VERSION 5.8 ;
BUSBITCHARS "[]" ;
DIVIDERCHAR "/" ;
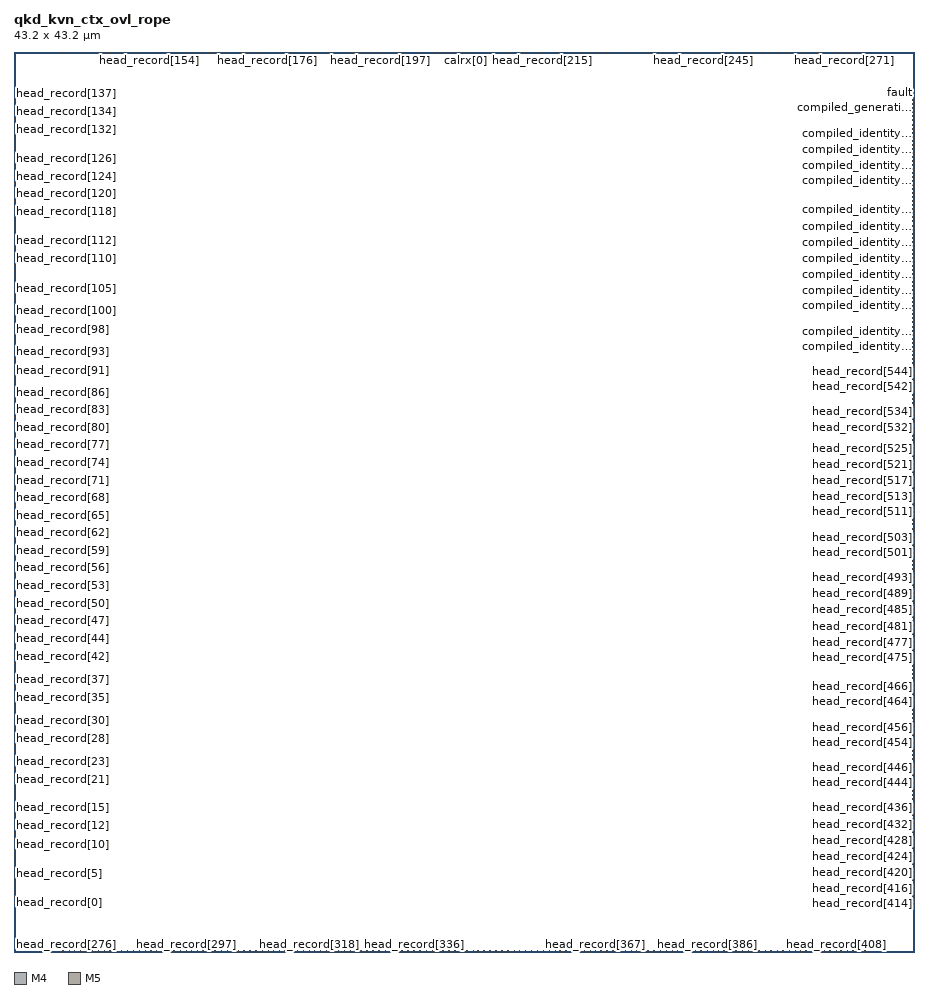
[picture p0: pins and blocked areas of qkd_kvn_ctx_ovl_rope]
MACRO qkd_kvn_ctx_ovl_rope
  CLASS BLOCK ;
  ORIGIN 0 0 ;
  SIZE 43.200000 BY 43.200000 ;
  SYMMETRY X Y ;
  PIN head_record[0]
    DIRECTION INPUT ;
    USE SIGNAL ;
    PORT
      LAYER M4 ;
      RECT 0.000000 2.352000 0.084000 2.376000 ;
    END
  END head_record[0]
  PIN head_record[1]
    DIRECTION INPUT ;
    USE SIGNAL ;
    PORT
      LAYER M4 ;
      RECT 0.000000 2.640000 0.084000 2.664000 ;
    END
  END head_record[1]
  PIN head_record[2]
    DIRECTION INPUT ;
    USE SIGNAL ;
    PORT
      LAYER M4 ;
      RECT 0.000000 2.880000 0.084000 2.904000 ;
    END
  END head_record[2]
  PIN head_record[3]
    DIRECTION INPUT ;
    USE SIGNAL ;
    PORT
      LAYER M4 ;
      RECT 0.000000 3.168000 0.084000 3.192000 ;
    END
  END head_record[3]
  PIN head_record[4]
    DIRECTION INPUT ;
    USE SIGNAL ;
    PORT
      LAYER M4 ;
      RECT 0.000000 3.456000 0.084000 3.480000 ;
    END
  END head_record[4]
  PIN head_record[5]
    DIRECTION INPUT ;
    USE SIGNAL ;
    PORT
      LAYER M4 ;
      RECT 0.000000 3.744000 0.084000 3.768000 ;
    END
  END head_record[5]
  PIN head_record[6]
    DIRECTION INPUT ;
    USE SIGNAL ;
    PORT
      LAYER M4 ;
      RECT 0.000000 4.032000 0.084000 4.056000 ;
    END
  END head_record[6]
  PIN head_record[7]
    DIRECTION INPUT ;
    USE SIGNAL ;
    PORT
      LAYER M4 ;
      RECT 0.000000 4.320000 0.084000 4.344000 ;
    END
  END head_record[7]
  PIN head_record[8]
    DIRECTION INPUT ;
    USE SIGNAL ;
    PORT
      LAYER M4 ;
      RECT 0.000000 4.608000 0.084000 4.632000 ;
    END
  END head_record[8]
  PIN head_record[9]
    DIRECTION INPUT ;
    USE SIGNAL ;
    PORT
      LAYER M4 ;
      RECT 0.000000 4.848000 0.084000 4.872000 ;
    END
  END head_record[9]
  PIN head_record[10]
    DIRECTION INPUT ;
    USE SIGNAL ;
    PORT
      LAYER M4 ;
      RECT 0.000000 5.136000 0.084000 5.160000 ;
    END
  END head_record[10]
  PIN head_record[11]
    DIRECTION INPUT ;
    USE SIGNAL ;
    PORT
      LAYER M4 ;
      RECT 0.000000 5.424000 0.084000 5.448000 ;
    END
  END head_record[11]
  PIN head_record[12]
    DIRECTION INPUT ;
    USE SIGNAL ;
    PORT
      LAYER M4 ;
      RECT 0.000000 5.712000 0.084000 5.736000 ;
    END
  END head_record[12]
  PIN head_record[13]
    DIRECTION INPUT ;
    USE SIGNAL ;
    PORT
      LAYER M4 ;
      RECT 0.000000 6.000000 0.084000 6.024000 ;
    END
  END head_record[13]
  PIN head_record[14]
    DIRECTION INPUT ;
    USE SIGNAL ;
    PORT
      LAYER M4 ;
      RECT 0.000000 6.288000 0.084000 6.312000 ;
    END
  END head_record[14]
  PIN head_record[15]
    DIRECTION INPUT ;
    USE SIGNAL ;
    PORT
      LAYER M4 ;
      RECT 0.000000 6.576000 0.084000 6.600000 ;
    END
  END head_record[15]
  PIN head_record[16]
    DIRECTION INPUT ;
    USE SIGNAL ;
    PORT
      LAYER M4 ;
      RECT 0.000000 6.816000 0.084000 6.840000 ;
    END
  END head_record[16]
  PIN head_record[17]
    DIRECTION INPUT ;
    USE SIGNAL ;
    PORT
      LAYER M4 ;
      RECT 0.000000 7.104000 0.084000 7.128000 ;
    END
  END head_record[17]
  PIN head_record[18]
    DIRECTION INPUT ;
    USE SIGNAL ;
    PORT
      LAYER M4 ;
      RECT 0.000000 7.392000 0.084000 7.416000 ;
    END
  END head_record[18]
  PIN head_record[19]
    DIRECTION INPUT ;
    USE SIGNAL ;
    PORT
      LAYER M4 ;
      RECT 0.000000 7.680000 0.084000 7.704000 ;
    END
  END head_record[19]
  PIN head_record[20]
    DIRECTION INPUT ;
    USE SIGNAL ;
    PORT
      LAYER M4 ;
      RECT 0.000000 7.968000 0.084000 7.992000 ;
    END
  END head_record[20]
  PIN head_record[21]
    DIRECTION INPUT ;
    USE SIGNAL ;
    PORT
      LAYER M4 ;
      RECT 0.000000 8.256000 0.084000 8.280000 ;
    END
  END head_record[21]
  PIN head_record[22]
    DIRECTION INPUT ;
    USE SIGNAL ;
    PORT
      LAYER M4 ;
      RECT 0.000000 8.496000 0.084000 8.520000 ;
    END
  END head_record[22]
  PIN head_record[23]
    DIRECTION INPUT ;
    USE SIGNAL ;
    PORT
      LAYER M4 ;
      RECT 0.000000 8.784000 0.084000 8.808000 ;
    END
  END head_record[23]
  PIN head_record[24]
    DIRECTION INPUT ;
    USE SIGNAL ;
    PORT
      LAYER M4 ;
      RECT 0.000000 9.072000 0.084000 9.096000 ;
    END
  END head_record[24]
  PIN head_record[25]
    DIRECTION INPUT ;
    USE SIGNAL ;
    PORT
      LAYER M4 ;
      RECT 0.000000 9.360000 0.084000 9.384000 ;
    END
  END head_record[25]
  PIN head_record[26]
    DIRECTION INPUT ;
    USE SIGNAL ;
    PORT
      LAYER M4 ;
      RECT 0.000000 9.648000 0.084000 9.672000 ;
    END
  END head_record[26]
  PIN head_record[27]
    DIRECTION INPUT ;
    USE SIGNAL ;
    PORT
      LAYER M4 ;
      RECT 0.000000 9.936000 0.084000 9.960000 ;
    END
  END head_record[27]
  PIN head_record[28]
    DIRECTION INPUT ;
    USE SIGNAL ;
    PORT
      LAYER M4 ;
      RECT 0.000000 10.224000 0.084000 10.248000 ;
    END
  END head_record[28]
  PIN head_record[29]
    DIRECTION INPUT ;
    USE SIGNAL ;
    PORT
      LAYER M4 ;
      RECT 0.000000 10.464000 0.084000 10.488000 ;
    END
  END head_record[29]
  PIN head_record[30]
    DIRECTION INPUT ;
    USE SIGNAL ;
    PORT
      LAYER M4 ;
      RECT 0.000000 10.752000 0.084000 10.776000 ;
    END
  END head_record[30]
  PIN head_record[31]
    DIRECTION INPUT ;
    USE SIGNAL ;
    PORT
      LAYER M4 ;
      RECT 0.000000 11.040000 0.084000 11.064000 ;
    END
  END head_record[31]
  PIN head_record[32]
    DIRECTION INPUT ;
    USE SIGNAL ;
    PORT
      LAYER M4 ;
      RECT 0.000000 11.328000 0.084000 11.352000 ;
    END
  END head_record[32]
  PIN head_record[33]
    DIRECTION INPUT ;
    USE SIGNAL ;
    PORT
      LAYER M4 ;
      RECT 0.000000 11.616000 0.084000 11.640000 ;
    END
  END head_record[33]
  PIN head_record[34]
    DIRECTION INPUT ;
    USE SIGNAL ;
    PORT
      LAYER M4 ;
      RECT 0.000000 11.904000 0.084000 11.928000 ;
    END
  END head_record[34]
  PIN head_record[35]
    DIRECTION INPUT ;
    USE SIGNAL ;
    PORT
      LAYER M4 ;
      RECT 0.000000 12.192000 0.084000 12.216000 ;
    END
  END head_record[35]
  PIN head_record[36]
    DIRECTION INPUT ;
    USE SIGNAL ;
    PORT
      LAYER M4 ;
      RECT 0.000000 12.432000 0.084000 12.456000 ;
    END
  END head_record[36]
  PIN head_record[37]
    DIRECTION INPUT ;
    USE SIGNAL ;
    PORT
      LAYER M4 ;
      RECT 0.000000 12.720000 0.084000 12.744000 ;
    END
  END head_record[37]
  PIN head_record[38]
    DIRECTION INPUT ;
    USE SIGNAL ;
    PORT
      LAYER M4 ;
      RECT 0.000000 13.008000 0.084000 13.032000 ;
    END
  END head_record[38]
  PIN head_record[39]
    DIRECTION INPUT ;
    USE SIGNAL ;
    PORT
      LAYER M4 ;
      RECT 0.000000 13.296000 0.084000 13.320000 ;
    END
  END head_record[39]
  PIN head_record[40]
    DIRECTION INPUT ;
    USE SIGNAL ;
    PORT
      LAYER M4 ;
      RECT 0.000000 13.584000 0.084000 13.608000 ;
    END
  END head_record[40]
  PIN head_record[41]
    DIRECTION INPUT ;
    USE SIGNAL ;
    PORT
      LAYER M4 ;
      RECT 0.000000 13.872000 0.084000 13.896000 ;
    END
  END head_record[41]
  PIN head_record[42]
    DIRECTION INPUT ;
    USE SIGNAL ;
    PORT
      LAYER M4 ;
      RECT 0.000000 14.160000 0.084000 14.184000 ;
    END
  END head_record[42]
  PIN head_record[43]
    DIRECTION INPUT ;
    USE SIGNAL ;
    PORT
      LAYER M4 ;
      RECT 0.000000 14.400000 0.084000 14.424000 ;
    END
  END head_record[43]
  PIN head_record[44]
    DIRECTION INPUT ;
    USE SIGNAL ;
    PORT
      LAYER M4 ;
      RECT 0.000000 14.688000 0.084000 14.712000 ;
    END
  END head_record[44]
  PIN head_record[45]
    DIRECTION INPUT ;
    USE SIGNAL ;
    PORT
      LAYER M4 ;
      RECT 0.000000 14.976000 0.084000 15.000000 ;
    END
  END head_record[45]
  PIN head_record[46]
    DIRECTION INPUT ;
    USE SIGNAL ;
    PORT
      LAYER M4 ;
      RECT 0.000000 15.264000 0.084000 15.288000 ;
    END
  END head_record[46]
  PIN head_record[47]
    DIRECTION INPUT ;
    USE SIGNAL ;
    PORT
      LAYER M4 ;
      RECT 0.000000 15.552000 0.084000 15.576000 ;
    END
  END head_record[47]
  PIN head_record[48]
    DIRECTION INPUT ;
    USE SIGNAL ;
    PORT
      LAYER M4 ;
      RECT 0.000000 15.840000 0.084000 15.864000 ;
    END
  END head_record[48]
  PIN head_record[49]
    DIRECTION INPUT ;
    USE SIGNAL ;
    PORT
      LAYER M4 ;
      RECT 0.000000 16.128000 0.084000 16.152000 ;
    END
  END head_record[49]
  PIN head_record[50]
    DIRECTION INPUT ;
    USE SIGNAL ;
    PORT
      LAYER M4 ;
      RECT 0.000000 16.368000 0.084000 16.392000 ;
    END
  END head_record[50]
  PIN head_record[51]
    DIRECTION INPUT ;
    USE SIGNAL ;
    PORT
      LAYER M4 ;
      RECT 0.000000 16.656000 0.084000 16.680000 ;
    END
  END head_record[51]
  PIN head_record[52]
    DIRECTION INPUT ;
    USE SIGNAL ;
    PORT
      LAYER M4 ;
      RECT 0.000000 16.944000 0.084000 16.968000 ;
    END
  END head_record[52]
  PIN head_record[53]
    DIRECTION INPUT ;
    USE SIGNAL ;
    PORT
      LAYER M4 ;
      RECT 0.000000 17.232000 0.084000 17.256000 ;
    END
  END head_record[53]
  PIN head_record[54]
    DIRECTION INPUT ;
    USE SIGNAL ;
    PORT
      LAYER M4 ;
      RECT 0.000000 17.520000 0.084000 17.544000 ;
    END
  END head_record[54]
  PIN head_record[55]
    DIRECTION INPUT ;
    USE SIGNAL ;
    PORT
      LAYER M4 ;
      RECT 0.000000 17.808000 0.084000 17.832000 ;
    END
  END head_record[55]
  PIN head_record[56]
    DIRECTION INPUT ;
    USE SIGNAL ;
    PORT
      LAYER M4 ;
      RECT 0.000000 18.096000 0.084000 18.120000 ;
    END
  END head_record[56]
  PIN head_record[57]
    DIRECTION INPUT ;
    USE SIGNAL ;
    PORT
      LAYER M4 ;
      RECT 0.000000 18.336000 0.084000 18.360000 ;
    END
  END head_record[57]
  PIN head_record[58]
    DIRECTION INPUT ;
    USE SIGNAL ;
    PORT
      LAYER M4 ;
      RECT 0.000000 18.624000 0.084000 18.648000 ;
    END
  END head_record[58]
  PIN head_record[59]
    DIRECTION INPUT ;
    USE SIGNAL ;
    PORT
      LAYER M4 ;
      RECT 0.000000 18.912000 0.084000 18.936000 ;
    END
  END head_record[59]
  PIN head_record[60]
    DIRECTION INPUT ;
    USE SIGNAL ;
    PORT
      LAYER M4 ;
      RECT 0.000000 19.200000 0.084000 19.224000 ;
    END
  END head_record[60]
  PIN head_record[61]
    DIRECTION INPUT ;
    USE SIGNAL ;
    PORT
      LAYER M4 ;
      RECT 0.000000 19.488000 0.084000 19.512000 ;
    END
  END head_record[61]
  PIN head_record[62]
    DIRECTION INPUT ;
    USE SIGNAL ;
    PORT
      LAYER M4 ;
      RECT 0.000000 19.776000 0.084000 19.800000 ;
    END
  END head_record[62]
  PIN head_record[63]
    DIRECTION INPUT ;
    USE SIGNAL ;
    PORT
      LAYER M4 ;
      RECT 0.000000 20.064000 0.084000 20.088000 ;
    END
  END head_record[63]
  PIN head_record[64]
    DIRECTION INPUT ;
    USE SIGNAL ;
    PORT
      LAYER M4 ;
      RECT 0.000000 20.304000 0.084000 20.328000 ;
    END
  END head_record[64]
  PIN head_record[65]
    DIRECTION INPUT ;
    USE SIGNAL ;
    PORT
      LAYER M4 ;
      RECT 0.000000 20.592000 0.084000 20.616000 ;
    END
  END head_record[65]
  PIN head_record[66]
    DIRECTION INPUT ;
    USE SIGNAL ;
    PORT
      LAYER M4 ;
      RECT 0.000000 20.880000 0.084000 20.904000 ;
    END
  END head_record[66]
  PIN head_record[67]
    DIRECTION INPUT ;
    USE SIGNAL ;
    PORT
      LAYER M4 ;
      RECT 0.000000 21.168000 0.084000 21.192000 ;
    END
  END head_record[67]
  PIN head_record[68]
    DIRECTION INPUT ;
    USE SIGNAL ;
    PORT
      LAYER M4 ;
      RECT 0.000000 21.456000 0.084000 21.480000 ;
    END
  END head_record[68]
  PIN head_record[69]
    DIRECTION INPUT ;
    USE SIGNAL ;
    PORT
      LAYER M4 ;
      RECT 0.000000 21.744000 0.084000 21.768000 ;
    END
  END head_record[69]
  PIN head_record[70]
    DIRECTION INPUT ;
    USE SIGNAL ;
    PORT
      LAYER M4 ;
      RECT 0.000000 22.032000 0.084000 22.056000 ;
    END
  END head_record[70]
  PIN head_record[71]
    DIRECTION INPUT ;
    USE SIGNAL ;
    PORT
      LAYER M4 ;
      RECT 0.000000 22.272000 0.084000 22.296000 ;
    END
  END head_record[71]
  PIN head_record[72]
    DIRECTION INPUT ;
    USE SIGNAL ;
    PORT
      LAYER M4 ;
      RECT 0.000000 22.560000 0.084000 22.584000 ;
    END
  END head_record[72]
  PIN head_record[73]
    DIRECTION INPUT ;
    USE SIGNAL ;
    PORT
      LAYER M4 ;
      RECT 0.000000 22.848000 0.084000 22.872000 ;
    END
  END head_record[73]
  PIN head_record[74]
    DIRECTION INPUT ;
    USE SIGNAL ;
    PORT
      LAYER M4 ;
      RECT 0.000000 23.136000 0.084000 23.160000 ;
    END
  END head_record[74]
  PIN head_record[75]
    DIRECTION INPUT ;
    USE SIGNAL ;
    PORT
      LAYER M4 ;
      RECT 0.000000 23.424000 0.084000 23.448000 ;
    END
  END head_record[75]
  PIN head_record[76]
    DIRECTION INPUT ;
    USE SIGNAL ;
    PORT
      LAYER M4 ;
      RECT 0.000000 23.712000 0.084000 23.736000 ;
    END
  END head_record[76]
  PIN head_record[77]
    DIRECTION INPUT ;
    USE SIGNAL ;
    PORT
      LAYER M4 ;
      RECT 0.000000 24.000000 0.084000 24.024000 ;
    END
  END head_record[77]
  PIN head_record[78]
    DIRECTION INPUT ;
    USE SIGNAL ;
    PORT
      LAYER M4 ;
      RECT 0.000000 24.240000 0.084000 24.264000 ;
    END
  END head_record[78]
  PIN head_record[79]
    DIRECTION INPUT ;
    USE SIGNAL ;
    PORT
      LAYER M4 ;
      RECT 0.000000 24.528000 0.084000 24.552000 ;
    END
  END head_record[79]
  PIN head_record[80]
    DIRECTION INPUT ;
    USE SIGNAL ;
    PORT
      LAYER M4 ;
      RECT 0.000000 24.816000 0.084000 24.840000 ;
    END
  END head_record[80]
  PIN head_record[81]
    DIRECTION INPUT ;
    USE SIGNAL ;
    PORT
      LAYER M4 ;
      RECT 0.000000 25.104000 0.084000 25.128000 ;
    END
  END head_record[81]
  PIN head_record[82]
    DIRECTION INPUT ;
    USE SIGNAL ;
    PORT
      LAYER M4 ;
      RECT 0.000000 25.392000 0.084000 25.416000 ;
    END
  END head_record[82]
  PIN head_record[83]
    DIRECTION INPUT ;
    USE SIGNAL ;
    PORT
      LAYER M4 ;
      RECT 0.000000 25.680000 0.084000 25.704000 ;
    END
  END head_record[83]
  PIN head_record[84]
    DIRECTION INPUT ;
    USE SIGNAL ;
    PORT
      LAYER M4 ;
      RECT 0.000000 25.968000 0.084000 25.992000 ;
    END
  END head_record[84]
  PIN head_record[85]
    DIRECTION INPUT ;
    USE SIGNAL ;
    PORT
      LAYER M4 ;
      RECT 0.000000 26.208000 0.084000 26.232000 ;
    END
  END head_record[85]
  PIN head_record[86]
    DIRECTION INPUT ;
    USE SIGNAL ;
    PORT
      LAYER M4 ;
      RECT 0.000000 26.496000 0.084000 26.520000 ;
    END
  END head_record[86]
  PIN head_record[87]
    DIRECTION INPUT ;
    USE SIGNAL ;
    PORT
      LAYER M4 ;
      RECT 0.000000 26.784000 0.084000 26.808000 ;
    END
  END head_record[87]
  PIN head_record[88]
    DIRECTION INPUT ;
    USE SIGNAL ;
    PORT
      LAYER M4 ;
      RECT 0.000000 27.072000 0.084000 27.096000 ;
    END
  END head_record[88]
  PIN head_record[89]
    DIRECTION INPUT ;
    USE SIGNAL ;
    PORT
      LAYER M4 ;
      RECT 0.000000 27.360000 0.084000 27.384000 ;
    END
  END head_record[89]
  PIN head_record[90]
    DIRECTION INPUT ;
    USE SIGNAL ;
    PORT
      LAYER M4 ;
      RECT 0.000000 27.648000 0.084000 27.672000 ;
    END
  END head_record[90]
  PIN head_record[91]
    DIRECTION INPUT ;
    USE SIGNAL ;
    PORT
      LAYER M4 ;
      RECT 0.000000 27.888000 0.084000 27.912000 ;
    END
  END head_record[91]
  PIN head_record[92]
    DIRECTION INPUT ;
    USE SIGNAL ;
    PORT
      LAYER M4 ;
      RECT 0.000000 28.176000 0.084000 28.200000 ;
    END
  END head_record[92]
  PIN head_record[93]
    DIRECTION INPUT ;
    USE SIGNAL ;
    PORT
      LAYER M4 ;
      RECT 0.000000 28.464000 0.084000 28.488000 ;
    END
  END head_record[93]
  PIN head_record[94]
    DIRECTION INPUT ;
    USE SIGNAL ;
    PORT
      LAYER M4 ;
      RECT 0.000000 28.752000 0.084000 28.776000 ;
    END
  END head_record[94]
  PIN head_record[95]
    DIRECTION INPUT ;
    USE SIGNAL ;
    PORT
      LAYER M4 ;
      RECT 0.000000 29.040000 0.084000 29.064000 ;
    END
  END head_record[95]
  PIN head_record[96]
    DIRECTION INPUT ;
    USE SIGNAL ;
    PORT
      LAYER M4 ;
      RECT 0.000000 29.328000 0.084000 29.352000 ;
    END
  END head_record[96]
  PIN head_record[97]
    DIRECTION INPUT ;
    USE SIGNAL ;
    PORT
      LAYER M4 ;
      RECT 0.000000 29.616000 0.084000 29.640000 ;
    END
  END head_record[97]
  PIN head_record[98]
    DIRECTION INPUT ;
    USE SIGNAL ;
    PORT
      LAYER M4 ;
      RECT 0.000000 29.856000 0.084000 29.880000 ;
    END
  END head_record[98]
  PIN head_record[99]
    DIRECTION INPUT ;
    USE SIGNAL ;
    PORT
      LAYER M4 ;
      RECT 0.000000 30.144000 0.084000 30.168000 ;
    END
  END head_record[99]
  PIN head_record[100]
    DIRECTION INPUT ;
    USE SIGNAL ;
    PORT
      LAYER M4 ;
      RECT 0.000000 30.432000 0.084000 30.456000 ;
    END
  END head_record[100]
  PIN head_record[101]
    DIRECTION INPUT ;
    USE SIGNAL ;
    PORT
      LAYER M4 ;
      RECT 0.000000 30.720000 0.084000 30.744000 ;
    END
  END head_record[101]
  PIN head_record[102]
    DIRECTION INPUT ;
    USE SIGNAL ;
    PORT
      LAYER M4 ;
      RECT 0.000000 31.008000 0.084000 31.032000 ;
    END
  END head_record[102]
  PIN head_record[103]
    DIRECTION INPUT ;
    USE SIGNAL ;
    PORT
      LAYER M4 ;
      RECT 0.000000 31.296000 0.084000 31.320000 ;
    END
  END head_record[103]
  PIN head_record[104]
    DIRECTION INPUT ;
    USE SIGNAL ;
    PORT
      LAYER M4 ;
      RECT 0.000000 31.584000 0.084000 31.608000 ;
    END
  END head_record[104]
  PIN head_record[105]
    DIRECTION INPUT ;
    USE SIGNAL ;
    PORT
      LAYER M4 ;
      RECT 0.000000 31.824000 0.084000 31.848000 ;
    END
  END head_record[105]
  PIN head_record[106]
    DIRECTION INPUT ;
    USE SIGNAL ;
    PORT
      LAYER M4 ;
      RECT 0.000000 32.112000 0.084000 32.136000 ;
    END
  END head_record[106]
  PIN head_record[107]
    DIRECTION INPUT ;
    USE SIGNAL ;
    PORT
      LAYER M4 ;
      RECT 0.000000 32.400000 0.084000 32.424000 ;
    END
  END head_record[107]
  PIN head_record[108]
    DIRECTION INPUT ;
    USE SIGNAL ;
    PORT
      LAYER M4 ;
      RECT 0.000000 32.688000 0.084000 32.712000 ;
    END
  END head_record[108]
  PIN head_record[109]
    DIRECTION INPUT ;
    USE SIGNAL ;
    PORT
      LAYER M4 ;
      RECT 0.000000 32.976000 0.084000 33.000000 ;
    END
  END head_record[109]
  PIN head_record[110]
    DIRECTION INPUT ;
    USE SIGNAL ;
    PORT
      LAYER M4 ;
      RECT 0.000000 33.264000 0.084000 33.288000 ;
    END
  END head_record[110]
  PIN head_record[111]
    DIRECTION INPUT ;
    USE SIGNAL ;
    PORT
      LAYER M4 ;
      RECT 0.000000 33.552000 0.084000 33.576000 ;
    END
  END head_record[111]
  PIN head_record[112]
    DIRECTION INPUT ;
    USE SIGNAL ;
    PORT
      LAYER M4 ;
      RECT 0.000000 33.792000 0.084000 33.816000 ;
    END
  END head_record[112]
  PIN head_record[113]
    DIRECTION INPUT ;
    USE SIGNAL ;
    PORT
      LAYER M4 ;
      RECT 0.000000 34.080000 0.084000 34.104000 ;
    END
  END head_record[113]
  PIN head_record[114]
    DIRECTION INPUT ;
    USE SIGNAL ;
    PORT
      LAYER M4 ;
      RECT 0.000000 34.368000 0.084000 34.392000 ;
    END
  END head_record[114]
  PIN head_record[115]
    DIRECTION INPUT ;
    USE SIGNAL ;
    PORT
      LAYER M4 ;
      RECT 0.000000 34.656000 0.084000 34.680000 ;
    END
  END head_record[115]
  PIN head_record[116]
    DIRECTION INPUT ;
    USE SIGNAL ;
    PORT
      LAYER M4 ;
      RECT 0.000000 34.944000 0.084000 34.968000 ;
    END
  END head_record[116]
  PIN head_record[117]
    DIRECTION INPUT ;
    USE SIGNAL ;
    PORT
      LAYER M4 ;
      RECT 0.000000 35.232000 0.084000 35.256000 ;
    END
  END head_record[117]
  PIN head_record[118]
    DIRECTION INPUT ;
    USE SIGNAL ;
    PORT
      LAYER M4 ;
      RECT 0.000000 35.520000 0.084000 35.544000 ;
    END
  END head_record[118]
  PIN head_record[119]
    DIRECTION INPUT ;
    USE SIGNAL ;
    PORT
      LAYER M4 ;
      RECT 0.000000 35.760000 0.084000 35.784000 ;
    END
  END head_record[119]
  PIN head_record[120]
    DIRECTION INPUT ;
    USE SIGNAL ;
    PORT
      LAYER M4 ;
      RECT 0.000000 36.048000 0.084000 36.072000 ;
    END
  END head_record[120]
  PIN head_record[121]
    DIRECTION INPUT ;
    USE SIGNAL ;
    PORT
      LAYER M4 ;
      RECT 0.000000 36.336000 0.084000 36.360000 ;
    END
  END head_record[121]
  PIN head_record[122]
    DIRECTION INPUT ;
    USE SIGNAL ;
    PORT
      LAYER M4 ;
      RECT 0.000000 36.624000 0.084000 36.648000 ;
    END
  END head_record[122]
  PIN head_record[123]
    DIRECTION INPUT ;
    USE SIGNAL ;
    PORT
      LAYER M4 ;
      RECT 0.000000 36.912000 0.084000 36.936000 ;
    END
  END head_record[123]
  PIN head_record[124]
    DIRECTION INPUT ;
    USE SIGNAL ;
    PORT
      LAYER M4 ;
      RECT 0.000000 37.200000 0.084000 37.224000 ;
    END
  END head_record[124]
  PIN head_record[125]
    DIRECTION INPUT ;
    USE SIGNAL ;
    PORT
      LAYER M4 ;
      RECT 0.000000 37.488000 0.084000 37.512000 ;
    END
  END head_record[125]
  PIN head_record[126]
    DIRECTION INPUT ;
    USE SIGNAL ;
    PORT
      LAYER M4 ;
      RECT 0.000000 37.728000 0.084000 37.752000 ;
    END
  END head_record[126]
  PIN head_record[127]
    DIRECTION INPUT ;
    USE SIGNAL ;
    PORT
      LAYER M4 ;
      RECT 0.000000 38.016000 0.084000 38.040000 ;
    END
  END head_record[127]
  PIN head_record[128]
    DIRECTION INPUT ;
    USE SIGNAL ;
    PORT
      LAYER M4 ;
      RECT 0.000000 38.304000 0.084000 38.328000 ;
    END
  END head_record[128]
  PIN head_record[129]
    DIRECTION INPUT ;
    USE SIGNAL ;
    PORT
      LAYER M4 ;
      RECT 0.000000 38.592000 0.084000 38.616000 ;
    END
  END head_record[129]
  PIN head_record[130]
    DIRECTION INPUT ;
    USE SIGNAL ;
    PORT
      LAYER M4 ;
      RECT 0.000000 38.880000 0.084000 38.904000 ;
    END
  END head_record[130]
  PIN head_record[131]
    DIRECTION INPUT ;
    USE SIGNAL ;
    PORT
      LAYER M4 ;
      RECT 0.000000 39.168000 0.084000 39.192000 ;
    END
  END head_record[131]
  PIN head_record[132]
    DIRECTION INPUT ;
    USE SIGNAL ;
    PORT
      LAYER M4 ;
      RECT 0.000000 39.456000 0.084000 39.480000 ;
    END
  END head_record[132]
  PIN head_record[133]
    DIRECTION INPUT ;
    USE SIGNAL ;
    PORT
      LAYER M4 ;
      RECT 0.000000 39.696000 0.084000 39.720000 ;
    END
  END head_record[133]
  PIN head_record[134]
    DIRECTION INPUT ;
    USE SIGNAL ;
    PORT
      LAYER M4 ;
      RECT 0.000000 39.984000 0.084000 40.008000 ;
    END
  END head_record[134]
  PIN head_record[135]
    DIRECTION INPUT ;
    USE SIGNAL ;
    PORT
      LAYER M4 ;
      RECT 0.000000 40.272000 0.084000 40.296000 ;
    END
  END head_record[135]
  PIN head_record[136]
    DIRECTION INPUT ;
    USE SIGNAL ;
    PORT
      LAYER M4 ;
      RECT 0.000000 40.560000 0.084000 40.584000 ;
    END
  END head_record[136]
  PIN head_record[137]
    DIRECTION INPUT ;
    USE SIGNAL ;
    PORT
      LAYER M4 ;
      RECT 0.000000 40.848000 0.084000 40.872000 ;
    END
  END head_record[137]
  PIN head_record[138]
    DIRECTION INPUT ;
    USE SIGNAL ;
    PORT
      LAYER M5 ;
      RECT 2.304000 43.116000 2.328000 43.200000 ;
    END
  END head_record[138]
  PIN head_record[139]
    DIRECTION INPUT ;
    USE SIGNAL ;
    PORT
      LAYER M5 ;
      RECT 2.592000 43.116000 2.616000 43.200000 ;
    END
  END head_record[139]
  PIN head_record[140]
    DIRECTION INPUT ;
    USE SIGNAL ;
    PORT
      LAYER M5 ;
      RECT 2.832000 43.116000 2.856000 43.200000 ;
    END
  END head_record[140]
  PIN head_record[141]
    DIRECTION INPUT ;
    USE SIGNAL ;
    PORT
      LAYER M5 ;
      RECT 3.120000 43.116000 3.144000 43.200000 ;
    END
  END head_record[141]
  PIN head_record[142]
    DIRECTION INPUT ;
    USE SIGNAL ;
    PORT
      LAYER M5 ;
      RECT 3.360000 43.116000 3.384000 43.200000 ;
    END
  END head_record[142]
  PIN head_record[143]
    DIRECTION INPUT ;
    USE SIGNAL ;
    PORT
      LAYER M5 ;
      RECT 3.600000 43.116000 3.624000 43.200000 ;
    END
  END head_record[143]
  PIN head_record[144]
    DIRECTION INPUT ;
    USE SIGNAL ;
    PORT
      LAYER M5 ;
      RECT 3.888000 43.116000 3.912000 43.200000 ;
    END
  END head_record[144]
  PIN head_record[145]
    DIRECTION INPUT ;
    USE SIGNAL ;
    PORT
      LAYER M5 ;
      RECT 4.128000 43.116000 4.152000 43.200000 ;
    END
  END head_record[145]
  PIN head_record[146]
    DIRECTION INPUT ;
    USE SIGNAL ;
    PORT
      LAYER M5 ;
      RECT 4.416000 43.116000 4.440000 43.200000 ;
    END
  END head_record[146]
  PIN head_record[147]
    DIRECTION INPUT ;
    USE SIGNAL ;
    PORT
      LAYER M5 ;
      RECT 4.656000 43.116000 4.680000 43.200000 ;
    END
  END head_record[147]
  PIN head_record[148]
    DIRECTION INPUT ;
    USE SIGNAL ;
    PORT
      LAYER M5 ;
      RECT 4.896000 43.116000 4.920000 43.200000 ;
    END
  END head_record[148]
  PIN head_record[149]
    DIRECTION INPUT ;
    USE SIGNAL ;
    PORT
      LAYER M5 ;
      RECT 5.184000 43.116000 5.208000 43.200000 ;
    END
  END head_record[149]
  PIN head_record[150]
    DIRECTION INPUT ;
    USE SIGNAL ;
    PORT
      LAYER M5 ;
      RECT 5.424000 43.116000 5.448000 43.200000 ;
    END
  END head_record[150]
  PIN head_record[151]
    DIRECTION INPUT ;
    USE SIGNAL ;
    PORT
      LAYER M5 ;
      RECT 5.664000 43.116000 5.688000 43.200000 ;
    END
  END head_record[151]
  PIN head_record[152]
    DIRECTION INPUT ;
    USE SIGNAL ;
    PORT
      LAYER M5 ;
      RECT 5.952000 43.116000 5.976000 43.200000 ;
    END
  END head_record[152]
  PIN head_record[153]
    DIRECTION INPUT ;
    USE SIGNAL ;
    PORT
      LAYER M5 ;
      RECT 6.192000 43.116000 6.216000 43.200000 ;
    END
  END head_record[153]
  PIN head_record[154]
    DIRECTION INPUT ;
    USE SIGNAL ;
    PORT
      LAYER M5 ;
      RECT 6.480000 43.116000 6.504000 43.200000 ;
    END
  END head_record[154]
  PIN head_record[155]
    DIRECTION INPUT ;
    USE SIGNAL ;
    PORT
      LAYER M5 ;
      RECT 6.720000 43.116000 6.744000 43.200000 ;
    END
  END head_record[155]
  PIN head_record[156]
    DIRECTION INPUT ;
    USE SIGNAL ;
    PORT
      LAYER M5 ;
      RECT 6.960000 43.116000 6.984000 43.200000 ;
    END
  END head_record[156]
  PIN head_record[157]
    DIRECTION INPUT ;
    USE SIGNAL ;
    PORT
      LAYER M5 ;
      RECT 7.248000 43.116000 7.272000 43.200000 ;
    END
  END head_record[157]
  PIN head_record[158]
    DIRECTION INPUT ;
    USE SIGNAL ;
    PORT
      LAYER M5 ;
      RECT 7.488000 43.116000 7.512000 43.200000 ;
    END
  END head_record[158]
  PIN head_record[159]
    DIRECTION INPUT ;
    USE SIGNAL ;
    PORT
      LAYER M5 ;
      RECT 7.776000 43.116000 7.800000 43.200000 ;
    END
  END head_record[159]
  PIN head_record[160]
    DIRECTION INPUT ;
    USE SIGNAL ;
    PORT
      LAYER M5 ;
      RECT 8.016000 43.116000 8.040000 43.200000 ;
    END
  END head_record[160]
  PIN head_record[161]
    DIRECTION INPUT ;
    USE SIGNAL ;
    PORT
      LAYER M5 ;
      RECT 8.256000 43.116000 8.280000 43.200000 ;
    END
  END head_record[161]
  PIN head_record[162]
    DIRECTION INPUT ;
    USE SIGNAL ;
    PORT
      LAYER M5 ;
      RECT 8.544000 43.116000 8.568000 43.200000 ;
    END
  END head_record[162]
  PIN head_record[163]
    DIRECTION INPUT ;
    USE SIGNAL ;
    PORT
      LAYER M5 ;
      RECT 8.784000 43.116000 8.808000 43.200000 ;
    END
  END head_record[163]
  PIN head_record[164]
    DIRECTION INPUT ;
    USE SIGNAL ;
    PORT
      LAYER M5 ;
      RECT 9.024000 43.116000 9.048000 43.200000 ;
    END
  END head_record[164]
  PIN head_record[165]
    DIRECTION INPUT ;
    USE SIGNAL ;
    PORT
      LAYER M5 ;
      RECT 9.312000 43.116000 9.336000 43.200000 ;
    END
  END head_record[165]
  PIN head_record[166]
    DIRECTION INPUT ;
    USE SIGNAL ;
    PORT
      LAYER M5 ;
      RECT 9.552000 43.116000 9.576000 43.200000 ;
    END
  END head_record[166]
  PIN head_record[167]
    DIRECTION INPUT ;
    USE SIGNAL ;
    PORT
      LAYER M5 ;
      RECT 9.840000 43.116000 9.864000 43.200000 ;
    END
  END head_record[167]
  PIN head_record[168]
    DIRECTION INPUT ;
    USE SIGNAL ;
    PORT
      LAYER M5 ;
      RECT 10.080000 43.116000 10.104000 43.200000 ;
    END
  END head_record[168]
  PIN head_record[169]
    DIRECTION INPUT ;
    USE SIGNAL ;
    PORT
      LAYER M5 ;
      RECT 10.320000 43.116000 10.344000 43.200000 ;
    END
  END head_record[169]
  PIN head_record[170]
    DIRECTION INPUT ;
    USE SIGNAL ;
    PORT
      LAYER M5 ;
      RECT 10.608000 43.116000 10.632000 43.200000 ;
    END
  END head_record[170]
  PIN head_record[171]
    DIRECTION INPUT ;
    USE SIGNAL ;
    PORT
      LAYER M5 ;
      RECT 10.848000 43.116000 10.872000 43.200000 ;
    END
  END head_record[171]
  PIN head_record[172]
    DIRECTION INPUT ;
    USE SIGNAL ;
    PORT
      LAYER M5 ;
      RECT 11.136000 43.116000 11.160000 43.200000 ;
    END
  END head_record[172]
  PIN head_record[173]
    DIRECTION INPUT ;
    USE SIGNAL ;
    PORT
      LAYER M5 ;
      RECT 11.376000 43.116000 11.400000 43.200000 ;
    END
  END head_record[173]
  PIN head_record[174]
    DIRECTION INPUT ;
    USE SIGNAL ;
    PORT
      LAYER M5 ;
      RECT 11.616000 43.116000 11.640000 43.200000 ;
    END
  END head_record[174]
  PIN head_record[175]
    DIRECTION INPUT ;
    USE SIGNAL ;
    PORT
      LAYER M5 ;
      RECT 11.904000 43.116000 11.928000 43.200000 ;
    END
  END head_record[175]
  PIN head_record[176]
    DIRECTION INPUT ;
    USE SIGNAL ;
    PORT
      LAYER M5 ;
      RECT 12.144000 43.116000 12.168000 43.200000 ;
    END
  END head_record[176]
  PIN head_record[177]
    DIRECTION INPUT ;
    USE SIGNAL ;
    PORT
      LAYER M5 ;
      RECT 12.432000 43.116000 12.456000 43.200000 ;
    END
  END head_record[177]
  PIN head_record[178]
    DIRECTION INPUT ;
    USE SIGNAL ;
    PORT
      LAYER M5 ;
      RECT 12.672000 43.116000 12.696000 43.200000 ;
    END
  END head_record[178]
  PIN head_record[179]
    DIRECTION INPUT ;
    USE SIGNAL ;
    PORT
      LAYER M5 ;
      RECT 12.912000 43.116000 12.936000 43.200000 ;
    END
  END head_record[179]
  PIN head_record[180]
    DIRECTION INPUT ;
    USE SIGNAL ;
    PORT
      LAYER M5 ;
      RECT 13.200000 43.116000 13.224000 43.200000 ;
    END
  END head_record[180]
  PIN head_record[181]
    DIRECTION INPUT ;
    USE SIGNAL ;
    PORT
      LAYER M5 ;
      RECT 13.440000 43.116000 13.464000 43.200000 ;
    END
  END head_record[181]
  PIN head_record[182]
    DIRECTION INPUT ;
    USE SIGNAL ;
    PORT
      LAYER M5 ;
      RECT 13.680000 43.116000 13.704000 43.200000 ;
    END
  END head_record[182]
  PIN head_record[183]
    DIRECTION INPUT ;
    USE SIGNAL ;
    PORT
      LAYER M5 ;
      RECT 13.968000 43.116000 13.992000 43.200000 ;
    END
  END head_record[183]
  PIN head_record[184]
    DIRECTION INPUT ;
    USE SIGNAL ;
    PORT
      LAYER M5 ;
      RECT 14.208000 43.116000 14.232000 43.200000 ;
    END
  END head_record[184]
  PIN head_record[185]
    DIRECTION INPUT ;
    USE SIGNAL ;
    PORT
      LAYER M5 ;
      RECT 14.496000 43.116000 14.520000 43.200000 ;
    END
  END head_record[185]
  PIN head_record[186]
    DIRECTION INPUT ;
    USE SIGNAL ;
    PORT
      LAYER M5 ;
      RECT 14.736000 43.116000 14.760000 43.200000 ;
    END
  END head_record[186]
  PIN head_record[187]
    DIRECTION INPUT ;
    USE SIGNAL ;
    PORT
      LAYER M5 ;
      RECT 14.976000 43.116000 15.000000 43.200000 ;
    END
  END head_record[187]
  PIN head_record[188]
    DIRECTION INPUT ;
    USE SIGNAL ;
    PORT
      LAYER M5 ;
      RECT 15.264000 43.116000 15.288000 43.200000 ;
    END
  END head_record[188]
  PIN head_record[189]
    DIRECTION INPUT ;
    USE SIGNAL ;
    PORT
      LAYER M5 ;
      RECT 15.504000 43.116000 15.528000 43.200000 ;
    END
  END head_record[189]
  PIN head_record[190]
    DIRECTION INPUT ;
    USE SIGNAL ;
    PORT
      LAYER M5 ;
      RECT 15.792000 43.116000 15.816000 43.200000 ;
    END
  END head_record[190]
  PIN head_record[191]
    DIRECTION INPUT ;
    USE SIGNAL ;
    PORT
      LAYER M5 ;
      RECT 16.032000 43.116000 16.056000 43.200000 ;
    END
  END head_record[191]
  PIN head_record[192]
    DIRECTION INPUT ;
    USE SIGNAL ;
    PORT
      LAYER M5 ;
      RECT 16.272000 43.116000 16.296000 43.200000 ;
    END
  END head_record[192]
  PIN head_record[193]
    DIRECTION INPUT ;
    USE SIGNAL ;
    PORT
      LAYER M5 ;
      RECT 16.560000 43.116000 16.584000 43.200000 ;
    END
  END head_record[193]
  PIN head_record[194]
    DIRECTION INPUT ;
    USE SIGNAL ;
    PORT
      LAYER M5 ;
      RECT 16.800000 43.116000 16.824000 43.200000 ;
    END
  END head_record[194]
  PIN head_record[195]
    DIRECTION INPUT ;
    USE SIGNAL ;
    PORT
      LAYER M5 ;
      RECT 17.040000 43.116000 17.064000 43.200000 ;
    END
  END head_record[195]
  PIN head_record[196]
    DIRECTION INPUT ;
    USE SIGNAL ;
    PORT
      LAYER M5 ;
      RECT 17.328000 43.116000 17.352000 43.200000 ;
    END
  END head_record[196]
  PIN head_record[197]
    DIRECTION INPUT ;
    USE SIGNAL ;
    PORT
      LAYER M5 ;
      RECT 17.568000 43.116000 17.592000 43.200000 ;
    END
  END head_record[197]
  PIN head_record[198]
    DIRECTION INPUT ;
    USE SIGNAL ;
    PORT
      LAYER M5 ;
      RECT 17.856000 43.116000 17.880000 43.200000 ;
    END
  END head_record[198]
  PIN head_record[199]
    DIRECTION INPUT ;
    USE SIGNAL ;
    PORT
      LAYER M5 ;
      RECT 18.096000 43.116000 18.120000 43.200000 ;
    END
  END head_record[199]
  PIN head_record[200]
    DIRECTION INPUT ;
    USE SIGNAL ;
    PORT
      LAYER M5 ;
      RECT 18.336000 43.116000 18.360000 43.200000 ;
    END
  END head_record[200]
  PIN head_record[201]
    DIRECTION INPUT ;
    USE SIGNAL ;
    PORT
      LAYER M5 ;
      RECT 18.624000 43.116000 18.648000 43.200000 ;
    END
  END head_record[201]
  PIN head_record[202]
    DIRECTION INPUT ;
    USE SIGNAL ;
    PORT
      LAYER M5 ;
      RECT 18.864000 43.116000 18.888000 43.200000 ;
    END
  END head_record[202]
  PIN head_record[203]
    DIRECTION INPUT ;
    USE SIGNAL ;
    PORT
      LAYER M5 ;
      RECT 19.152000 43.116000 19.176000 43.200000 ;
    END
  END head_record[203]
  PIN head_record[204]
    DIRECTION INPUT ;
    USE SIGNAL ;
    PORT
      LAYER M5 ;
      RECT 19.392000 43.116000 19.416000 43.200000 ;
    END
  END head_record[204]
  PIN head_record[205]
    DIRECTION INPUT ;
    USE SIGNAL ;
    PORT
      LAYER M5 ;
      RECT 19.632000 43.116000 19.656000 43.200000 ;
    END
  END head_record[205]
  PIN head_record[206]
    DIRECTION INPUT ;
    USE SIGNAL ;
    PORT
      LAYER M5 ;
      RECT 19.920000 43.116000 19.944000 43.200000 ;
    END
  END head_record[206]
  PIN ck
    DIRECTION INPUT ;
    USE CLOCK ;
    PORT
      LAYER M5 ;
      RECT 20.160000 43.116000 20.184000 43.200000 ;
    END
  END ck
  PIN rst_n
    DIRECTION INPUT ;
    USE SIGNAL ;
    PORT
      LAYER M5 ;
      RECT 20.448000 43.116000 20.472000 43.200000 ;
    END
  END rst_n
  PIN ovl_users[0]
    DIRECTION INPUT ;
    USE SIGNAL ;
    PORT
      LAYER M5 ;
      RECT 20.688000 43.116000 20.712000 43.200000 ;
    END
  END ovl_users[0]
  PIN ovl_users[1]
    DIRECTION INPUT ;
    USE SIGNAL ;
    PORT
      LAYER M5 ;
      RECT 20.928000 43.116000 20.952000 43.200000 ;
    END
  END ovl_users[1]
  PIN ovl_users[2]
    DIRECTION INPUT ;
    USE SIGNAL ;
    PORT
      LAYER M5 ;
      RECT 21.216000 43.116000 21.240000 43.200000 ;
    END
  END ovl_users[2]
  PIN ovl_users[3]
    DIRECTION INPUT ;
    USE SIGNAL ;
    PORT
      LAYER M5 ;
      RECT 21.456000 43.116000 21.480000 43.200000 ;
    END
  END ovl_users[3]
  PIN calrx[0]
    DIRECTION INPUT ;
    USE SIGNAL ;
    PORT
      LAYER M5 ;
      RECT 21.696000 43.116000 21.720000 43.200000 ;
    END
  END calrx[0]
  PIN calrx[1]
    DIRECTION INPUT ;
    USE SIGNAL ;
    PORT
      LAYER M5 ;
      RECT 21.984000 43.116000 22.008000 43.200000 ;
    END
  END calrx[1]
  PIN calrx[2]
    DIRECTION INPUT ;
    USE SIGNAL ;
    PORT
      LAYER M5 ;
      RECT 22.224000 43.116000 22.248000 43.200000 ;
    END
  END calrx[2]
  PIN calrx[3]
    DIRECTION INPUT ;
    USE SIGNAL ;
    PORT
      LAYER M5 ;
      RECT 22.512000 43.116000 22.536000 43.200000 ;
    END
  END calrx[3]
  PIN adm_done
    DIRECTION INPUT ;
    USE SIGNAL ;
    PORT
      LAYER M5 ;
      RECT 22.752000 43.116000 22.776000 43.200000 ;
    END
  END adm_done
  PIN reseed
    DIRECTION INPUT ;
    USE SIGNAL ;
    PORT
      LAYER M5 ;
      RECT 22.992000 43.116000 23.016000 43.200000 ;
    END
  END reseed
  PIN head_record[207]
    DIRECTION INPUT ;
    USE SIGNAL ;
    PORT
      LAYER M5 ;
      RECT 23.280000 43.116000 23.304000 43.200000 ;
    END
  END head_record[207]
  PIN head_record[208]
    DIRECTION INPUT ;
    USE SIGNAL ;
    PORT
      LAYER M5 ;
      RECT 23.520000 43.116000 23.544000 43.200000 ;
    END
  END head_record[208]
  PIN head_record[209]
    DIRECTION INPUT ;
    USE SIGNAL ;
    PORT
      LAYER M5 ;
      RECT 23.808000 43.116000 23.832000 43.200000 ;
    END
  END head_record[209]
  PIN head_record[210]
    DIRECTION INPUT ;
    USE SIGNAL ;
    PORT
      LAYER M5 ;
      RECT 24.048000 43.116000 24.072000 43.200000 ;
    END
  END head_record[210]
  PIN head_record[211]
    DIRECTION INPUT ;
    USE SIGNAL ;
    PORT
      LAYER M5 ;
      RECT 24.288000 43.116000 24.312000 43.200000 ;
    END
  END head_record[211]
  PIN head_record[212]
    DIRECTION INPUT ;
    USE SIGNAL ;
    PORT
      LAYER M5 ;
      RECT 24.576000 43.116000 24.600000 43.200000 ;
    END
  END head_record[212]
  PIN head_record[213]
    DIRECTION INPUT ;
    USE SIGNAL ;
    PORT
      LAYER M5 ;
      RECT 24.816000 43.116000 24.840000 43.200000 ;
    END
  END head_record[213]
  PIN head_record[214]
    DIRECTION INPUT ;
    USE SIGNAL ;
    PORT
      LAYER M5 ;
      RECT 25.056000 43.116000 25.080000 43.200000 ;
    END
  END head_record[214]
  PIN head_record[215]
    DIRECTION INPUT ;
    USE SIGNAL ;
    PORT
      LAYER M5 ;
      RECT 25.344000 43.116000 25.368000 43.200000 ;
    END
  END head_record[215]
  PIN head_record[216]
    DIRECTION INPUT ;
    USE SIGNAL ;
    PORT
      LAYER M5 ;
      RECT 25.584000 43.116000 25.608000 43.200000 ;
    END
  END head_record[216]
  PIN head_record[217]
    DIRECTION INPUT ;
    USE SIGNAL ;
    PORT
      LAYER M5 ;
      RECT 25.872000 43.116000 25.896000 43.200000 ;
    END
  END head_record[217]
  PIN head_record[218]
    DIRECTION INPUT ;
    USE SIGNAL ;
    PORT
      LAYER M5 ;
      RECT 26.112000 43.116000 26.136000 43.200000 ;
    END
  END head_record[218]
  PIN head_record[219]
    DIRECTION INPUT ;
    USE SIGNAL ;
    PORT
      LAYER M5 ;
      RECT 26.352000 43.116000 26.376000 43.200000 ;
    END
  END head_record[219]
  PIN head_record[220]
    DIRECTION INPUT ;
    USE SIGNAL ;
    PORT
      LAYER M5 ;
      RECT 26.640000 43.116000 26.664000 43.200000 ;
    END
  END head_record[220]
  PIN head_record[221]
    DIRECTION INPUT ;
    USE SIGNAL ;
    PORT
      LAYER M5 ;
      RECT 26.880000 43.116000 26.904000 43.200000 ;
    END
  END head_record[221]
  PIN head_record[222]
    DIRECTION INPUT ;
    USE SIGNAL ;
    PORT
      LAYER M5 ;
      RECT 27.168000 43.116000 27.192000 43.200000 ;
    END
  END head_record[222]
  PIN head_record[223]
    DIRECTION INPUT ;
    USE SIGNAL ;
    PORT
      LAYER M5 ;
      RECT 27.408000 43.116000 27.432000 43.200000 ;
    END
  END head_record[223]
  PIN head_record[224]
    DIRECTION INPUT ;
    USE SIGNAL ;
    PORT
      LAYER M5 ;
      RECT 27.648000 43.116000 27.672000 43.200000 ;
    END
  END head_record[224]
  PIN head_record[225]
    DIRECTION INPUT ;
    USE SIGNAL ;
    PORT
      LAYER M5 ;
      RECT 27.936000 43.116000 27.960000 43.200000 ;
    END
  END head_record[225]
  PIN head_record[226]
    DIRECTION INPUT ;
    USE SIGNAL ;
    PORT
      LAYER M5 ;
      RECT 28.176000 43.116000 28.200000 43.200000 ;
    END
  END head_record[226]
  PIN head_record[227]
    DIRECTION INPUT ;
    USE SIGNAL ;
    PORT
      LAYER M5 ;
      RECT 28.416000 43.116000 28.440000 43.200000 ;
    END
  END head_record[227]
  PIN head_record[228]
    DIRECTION INPUT ;
    USE SIGNAL ;
    PORT
      LAYER M5 ;
      RECT 28.704000 43.116000 28.728000 43.200000 ;
    END
  END head_record[228]
  PIN head_record[229]
    DIRECTION INPUT ;
    USE SIGNAL ;
    PORT
      LAYER M5 ;
      RECT 28.944000 43.116000 28.968000 43.200000 ;
    END
  END head_record[229]
  PIN head_record[230]
    DIRECTION INPUT ;
    USE SIGNAL ;
    PORT
      LAYER M5 ;
      RECT 29.232000 43.116000 29.256000 43.200000 ;
    END
  END head_record[230]
  PIN head_record[231]
    DIRECTION INPUT ;
    USE SIGNAL ;
    PORT
      LAYER M5 ;
      RECT 29.472000 43.116000 29.496000 43.200000 ;
    END
  END head_record[231]
  PIN head_record[232]
    DIRECTION INPUT ;
    USE SIGNAL ;
    PORT
      LAYER M5 ;
      RECT 29.712000 43.116000 29.736000 43.200000 ;
    END
  END head_record[232]
  PIN head_record[233]
    DIRECTION INPUT ;
    USE SIGNAL ;
    PORT
      LAYER M5 ;
      RECT 30.000000 43.116000 30.024000 43.200000 ;
    END
  END head_record[233]
  PIN head_record[234]
    DIRECTION INPUT ;
    USE SIGNAL ;
    PORT
      LAYER M5 ;
      RECT 30.240000 43.116000 30.264000 43.200000 ;
    END
  END head_record[234]
  PIN head_record[235]
    DIRECTION INPUT ;
    USE SIGNAL ;
    PORT
      LAYER M5 ;
      RECT 30.528000 43.116000 30.552000 43.200000 ;
    END
  END head_record[235]
  PIN head_record[236]
    DIRECTION INPUT ;
    USE SIGNAL ;
    PORT
      LAYER M5 ;
      RECT 30.768000 43.116000 30.792000 43.200000 ;
    END
  END head_record[236]
  PIN head_record[237]
    DIRECTION INPUT ;
    USE SIGNAL ;
    PORT
      LAYER M5 ;
      RECT 31.008000 43.116000 31.032000 43.200000 ;
    END
  END head_record[237]
  PIN head_record[238]
    DIRECTION INPUT ;
    USE SIGNAL ;
    PORT
      LAYER M5 ;
      RECT 31.296000 43.116000 31.320000 43.200000 ;
    END
  END head_record[238]
  PIN head_record[239]
    DIRECTION INPUT ;
    USE SIGNAL ;
    PORT
      LAYER M5 ;
      RECT 31.536000 43.116000 31.560000 43.200000 ;
    END
  END head_record[239]
  PIN head_record[240]
    DIRECTION INPUT ;
    USE SIGNAL ;
    PORT
      LAYER M5 ;
      RECT 31.824000 43.116000 31.848000 43.200000 ;
    END
  END head_record[240]
  PIN head_record[241]
    DIRECTION INPUT ;
    USE SIGNAL ;
    PORT
      LAYER M5 ;
      RECT 32.064000 43.116000 32.088000 43.200000 ;
    END
  END head_record[241]
  PIN head_record[242]
    DIRECTION INPUT ;
    USE SIGNAL ;
    PORT
      LAYER M5 ;
      RECT 32.304000 43.116000 32.328000 43.200000 ;
    END
  END head_record[242]
  PIN head_record[243]
    DIRECTION INPUT ;
    USE SIGNAL ;
    PORT
      LAYER M5 ;
      RECT 32.592000 43.116000 32.616000 43.200000 ;
    END
  END head_record[243]
  PIN head_record[244]
    DIRECTION INPUT ;
    USE SIGNAL ;
    PORT
      LAYER M5 ;
      RECT 32.832000 43.116000 32.856000 43.200000 ;
    END
  END head_record[244]
  PIN head_record[245]
    DIRECTION INPUT ;
    USE SIGNAL ;
    PORT
      LAYER M5 ;
      RECT 33.072000 43.116000 33.096000 43.200000 ;
    END
  END head_record[245]
  PIN head_record[246]
    DIRECTION INPUT ;
    USE SIGNAL ;
    PORT
      LAYER M5 ;
      RECT 33.360000 43.116000 33.384000 43.200000 ;
    END
  END head_record[246]
  PIN head_record[247]
    DIRECTION INPUT ;
    USE SIGNAL ;
    PORT
      LAYER M5 ;
      RECT 33.600000 43.116000 33.624000 43.200000 ;
    END
  END head_record[247]
  PIN head_record[248]
    DIRECTION INPUT ;
    USE SIGNAL ;
    PORT
      LAYER M5 ;
      RECT 33.888000 43.116000 33.912000 43.200000 ;
    END
  END head_record[248]
  PIN head_record[249]
    DIRECTION INPUT ;
    USE SIGNAL ;
    PORT
      LAYER M5 ;
      RECT 34.128000 43.116000 34.152000 43.200000 ;
    END
  END head_record[249]
  PIN head_record[250]
    DIRECTION INPUT ;
    USE SIGNAL ;
    PORT
      LAYER M5 ;
      RECT 34.368000 43.116000 34.392000 43.200000 ;
    END
  END head_record[250]
  PIN head_record[251]
    DIRECTION INPUT ;
    USE SIGNAL ;
    PORT
      LAYER M5 ;
      RECT 34.656000 43.116000 34.680000 43.200000 ;
    END
  END head_record[251]
  PIN head_record[252]
    DIRECTION INPUT ;
    USE SIGNAL ;
    PORT
      LAYER M5 ;
      RECT 34.896000 43.116000 34.920000 43.200000 ;
    END
  END head_record[252]
  PIN head_record[253]
    DIRECTION INPUT ;
    USE SIGNAL ;
    PORT
      LAYER M5 ;
      RECT 35.184000 43.116000 35.208000 43.200000 ;
    END
  END head_record[253]
  PIN head_record[254]
    DIRECTION INPUT ;
    USE SIGNAL ;
    PORT
      LAYER M5 ;
      RECT 35.424000 43.116000 35.448000 43.200000 ;
    END
  END head_record[254]
  PIN head_record[255]
    DIRECTION INPUT ;
    USE SIGNAL ;
    PORT
      LAYER M5 ;
      RECT 35.664000 43.116000 35.688000 43.200000 ;
    END
  END head_record[255]
  PIN head_record[256]
    DIRECTION INPUT ;
    USE SIGNAL ;
    PORT
      LAYER M5 ;
      RECT 35.952000 43.116000 35.976000 43.200000 ;
    END
  END head_record[256]
  PIN head_record[257]
    DIRECTION INPUT ;
    USE SIGNAL ;
    PORT
      LAYER M5 ;
      RECT 36.192000 43.116000 36.216000 43.200000 ;
    END
  END head_record[257]
  PIN head_record[258]
    DIRECTION INPUT ;
    USE SIGNAL ;
    PORT
      LAYER M5 ;
      RECT 36.432000 43.116000 36.456000 43.200000 ;
    END
  END head_record[258]
  PIN head_record[259]
    DIRECTION INPUT ;
    USE SIGNAL ;
    PORT
      LAYER M5 ;
      RECT 36.720000 43.116000 36.744000 43.200000 ;
    END
  END head_record[259]
  PIN head_record[260]
    DIRECTION INPUT ;
    USE SIGNAL ;
    PORT
      LAYER M5 ;
      RECT 36.960000 43.116000 36.984000 43.200000 ;
    END
  END head_record[260]
  PIN head_record[261]
    DIRECTION INPUT ;
    USE SIGNAL ;
    PORT
      LAYER M5 ;
      RECT 37.248000 43.116000 37.272000 43.200000 ;
    END
  END head_record[261]
  PIN head_record[262]
    DIRECTION INPUT ;
    USE SIGNAL ;
    PORT
      LAYER M5 ;
      RECT 37.488000 43.116000 37.512000 43.200000 ;
    END
  END head_record[262]
  PIN head_record[263]
    DIRECTION INPUT ;
    USE SIGNAL ;
    PORT
      LAYER M5 ;
      RECT 37.728000 43.116000 37.752000 43.200000 ;
    END
  END head_record[263]
  PIN head_record[264]
    DIRECTION INPUT ;
    USE SIGNAL ;
    PORT
      LAYER M5 ;
      RECT 38.016000 43.116000 38.040000 43.200000 ;
    END
  END head_record[264]
  PIN head_record[265]
    DIRECTION INPUT ;
    USE SIGNAL ;
    PORT
      LAYER M5 ;
      RECT 38.256000 43.116000 38.280000 43.200000 ;
    END
  END head_record[265]
  PIN head_record[266]
    DIRECTION INPUT ;
    USE SIGNAL ;
    PORT
      LAYER M5 ;
      RECT 38.544000 43.116000 38.568000 43.200000 ;
    END
  END head_record[266]
  PIN head_record[267]
    DIRECTION INPUT ;
    USE SIGNAL ;
    PORT
      LAYER M5 ;
      RECT 38.784000 43.116000 38.808000 43.200000 ;
    END
  END head_record[267]
  PIN head_record[268]
    DIRECTION INPUT ;
    USE SIGNAL ;
    PORT
      LAYER M5 ;
      RECT 39.024000 43.116000 39.048000 43.200000 ;
    END
  END head_record[268]
  PIN head_record[269]
    DIRECTION INPUT ;
    USE SIGNAL ;
    PORT
      LAYER M5 ;
      RECT 39.312000 43.116000 39.336000 43.200000 ;
    END
  END head_record[269]
  PIN head_record[270]
    DIRECTION INPUT ;
    USE SIGNAL ;
    PORT
      LAYER M5 ;
      RECT 39.552000 43.116000 39.576000 43.200000 ;
    END
  END head_record[270]
  PIN head_record[271]
    DIRECTION INPUT ;
    USE SIGNAL ;
    PORT
      LAYER M5 ;
      RECT 39.840000 43.116000 39.864000 43.200000 ;
    END
  END head_record[271]
  PIN head_record[272]
    DIRECTION INPUT ;
    USE SIGNAL ;
    PORT
      LAYER M5 ;
      RECT 40.080000 43.116000 40.104000 43.200000 ;
    END
  END head_record[272]
  PIN head_record[273]
    DIRECTION INPUT ;
    USE SIGNAL ;
    PORT
      LAYER M5 ;
      RECT 40.320000 43.116000 40.344000 43.200000 ;
    END
  END head_record[273]
  PIN head_record[274]
    DIRECTION INPUT ;
    USE SIGNAL ;
    PORT
      LAYER M5 ;
      RECT 40.608000 43.116000 40.632000 43.200000 ;
    END
  END head_record[274]
  PIN head_record[275]
    DIRECTION INPUT ;
    USE SIGNAL ;
    PORT
      LAYER M5 ;
      RECT 40.848000 43.116000 40.872000 43.200000 ;
    END
  END head_record[275]
  PIN head_record[276]
    DIRECTION INPUT ;
    USE SIGNAL ;
    PORT
      LAYER M5 ;
      RECT 2.352000 0.000000 2.376000 0.084000 ;
    END
  END head_record[276]
  PIN head_record[277]
    DIRECTION INPUT ;
    USE SIGNAL ;
    PORT
      LAYER M5 ;
      RECT 2.640000 0.000000 2.664000 0.084000 ;
    END
  END head_record[277]
  PIN head_record[278]
    DIRECTION INPUT ;
    USE SIGNAL ;
    PORT
      LAYER M5 ;
      RECT 2.880000 0.000000 2.904000 0.084000 ;
    END
  END head_record[278]
  PIN head_record[279]
    DIRECTION INPUT ;
    USE SIGNAL ;
    PORT
      LAYER M5 ;
      RECT 3.168000 0.000000 3.192000 0.084000 ;
    END
  END head_record[279]
  PIN head_record[280]
    DIRECTION INPUT ;
    USE SIGNAL ;
    PORT
      LAYER M5 ;
      RECT 3.456000 0.000000 3.480000 0.084000 ;
    END
  END head_record[280]
  PIN head_record[281]
    DIRECTION INPUT ;
    USE SIGNAL ;
    PORT
      LAYER M5 ;
      RECT 3.744000 0.000000 3.768000 0.084000 ;
    END
  END head_record[281]
  PIN head_record[282]
    DIRECTION INPUT ;
    USE SIGNAL ;
    PORT
      LAYER M5 ;
      RECT 4.032000 0.000000 4.056000 0.084000 ;
    END
  END head_record[282]
  PIN head_record[283]
    DIRECTION INPUT ;
    USE SIGNAL ;
    PORT
      LAYER M5 ;
      RECT 4.320000 0.000000 4.344000 0.084000 ;
    END
  END head_record[283]
  PIN head_record[284]
    DIRECTION INPUT ;
    USE SIGNAL ;
    PORT
      LAYER M5 ;
      RECT 4.608000 0.000000 4.632000 0.084000 ;
    END
  END head_record[284]
  PIN head_record[285]
    DIRECTION INPUT ;
    USE SIGNAL ;
    PORT
      LAYER M5 ;
      RECT 4.848000 0.000000 4.872000 0.084000 ;
    END
  END head_record[285]
  PIN head_record[286]
    DIRECTION INPUT ;
    USE SIGNAL ;
    PORT
      LAYER M5 ;
      RECT 5.136000 0.000000 5.160000 0.084000 ;
    END
  END head_record[286]
  PIN head_record[287]
    DIRECTION INPUT ;
    USE SIGNAL ;
    PORT
      LAYER M5 ;
      RECT 5.424000 0.000000 5.448000 0.084000 ;
    END
  END head_record[287]
  PIN head_record[288]
    DIRECTION INPUT ;
    USE SIGNAL ;
    PORT
      LAYER M5 ;
      RECT 5.712000 0.000000 5.736000 0.084000 ;
    END
  END head_record[288]
  PIN head_record[289]
    DIRECTION INPUT ;
    USE SIGNAL ;
    PORT
      LAYER M5 ;
      RECT 6.000000 0.000000 6.024000 0.084000 ;
    END
  END head_record[289]
  PIN head_record[290]
    DIRECTION INPUT ;
    USE SIGNAL ;
    PORT
      LAYER M5 ;
      RECT 6.288000 0.000000 6.312000 0.084000 ;
    END
  END head_record[290]
  PIN head_record[291]
    DIRECTION INPUT ;
    USE SIGNAL ;
    PORT
      LAYER M5 ;
      RECT 6.576000 0.000000 6.600000 0.084000 ;
    END
  END head_record[291]
  PIN head_record[292]
    DIRECTION INPUT ;
    USE SIGNAL ;
    PORT
      LAYER M5 ;
      RECT 6.816000 0.000000 6.840000 0.084000 ;
    END
  END head_record[292]
  PIN head_record[293]
    DIRECTION INPUT ;
    USE SIGNAL ;
    PORT
      LAYER M5 ;
      RECT 7.104000 0.000000 7.128000 0.084000 ;
    END
  END head_record[293]
  PIN head_record[294]
    DIRECTION INPUT ;
    USE SIGNAL ;
    PORT
      LAYER M5 ;
      RECT 7.392000 0.000000 7.416000 0.084000 ;
    END
  END head_record[294]
  PIN head_record[295]
    DIRECTION INPUT ;
    USE SIGNAL ;
    PORT
      LAYER M5 ;
      RECT 7.680000 0.000000 7.704000 0.084000 ;
    END
  END head_record[295]
  PIN head_record[296]
    DIRECTION INPUT ;
    USE SIGNAL ;
    PORT
      LAYER M5 ;
      RECT 7.968000 0.000000 7.992000 0.084000 ;
    END
  END head_record[296]
  PIN head_record[297]
    DIRECTION INPUT ;
    USE SIGNAL ;
    PORT
      LAYER M5 ;
      RECT 8.256000 0.000000 8.280000 0.084000 ;
    END
  END head_record[297]
  PIN head_record[298]
    DIRECTION INPUT ;
    USE SIGNAL ;
    PORT
      LAYER M5 ;
      RECT 8.496000 0.000000 8.520000 0.084000 ;
    END
  END head_record[298]
  PIN head_record[299]
    DIRECTION INPUT ;
    USE SIGNAL ;
    PORT
      LAYER M5 ;
      RECT 8.784000 0.000000 8.808000 0.084000 ;
    END
  END head_record[299]
  PIN head_record[300]
    DIRECTION INPUT ;
    USE SIGNAL ;
    PORT
      LAYER M5 ;
      RECT 9.072000 0.000000 9.096000 0.084000 ;
    END
  END head_record[300]
  PIN head_record[301]
    DIRECTION INPUT ;
    USE SIGNAL ;
    PORT
      LAYER M5 ;
      RECT 9.360000 0.000000 9.384000 0.084000 ;
    END
  END head_record[301]
  PIN head_record[302]
    DIRECTION INPUT ;
    USE SIGNAL ;
    PORT
      LAYER M5 ;
      RECT 9.648000 0.000000 9.672000 0.084000 ;
    END
  END head_record[302]
  PIN head_record[303]
    DIRECTION INPUT ;
    USE SIGNAL ;
    PORT
      LAYER M5 ;
      RECT 9.936000 0.000000 9.960000 0.084000 ;
    END
  END head_record[303]
  PIN head_record[304]
    DIRECTION INPUT ;
    USE SIGNAL ;
    PORT
      LAYER M5 ;
      RECT 10.224000 0.000000 10.248000 0.084000 ;
    END
  END head_record[304]
  PIN head_record[305]
    DIRECTION INPUT ;
    USE SIGNAL ;
    PORT
      LAYER M5 ;
      RECT 10.464000 0.000000 10.488000 0.084000 ;
    END
  END head_record[305]
  PIN head_record[306]
    DIRECTION INPUT ;
    USE SIGNAL ;
    PORT
      LAYER M5 ;
      RECT 10.752000 0.000000 10.776000 0.084000 ;
    END
  END head_record[306]
  PIN head_record[307]
    DIRECTION INPUT ;
    USE SIGNAL ;
    PORT
      LAYER M5 ;
      RECT 11.040000 0.000000 11.064000 0.084000 ;
    END
  END head_record[307]
  PIN head_record[308]
    DIRECTION INPUT ;
    USE SIGNAL ;
    PORT
      LAYER M5 ;
      RECT 11.328000 0.000000 11.352000 0.084000 ;
    END
  END head_record[308]
  PIN head_record[309]
    DIRECTION INPUT ;
    USE SIGNAL ;
    PORT
      LAYER M5 ;
      RECT 11.616000 0.000000 11.640000 0.084000 ;
    END
  END head_record[309]
  PIN head_record[310]
    DIRECTION INPUT ;
    USE SIGNAL ;
    PORT
      LAYER M5 ;
      RECT 11.904000 0.000000 11.928000 0.084000 ;
    END
  END head_record[310]
  PIN head_record[311]
    DIRECTION INPUT ;
    USE SIGNAL ;
    PORT
      LAYER M5 ;
      RECT 12.192000 0.000000 12.216000 0.084000 ;
    END
  END head_record[311]
  PIN head_record[312]
    DIRECTION INPUT ;
    USE SIGNAL ;
    PORT
      LAYER M5 ;
      RECT 12.432000 0.000000 12.456000 0.084000 ;
    END
  END head_record[312]
  PIN head_record[313]
    DIRECTION INPUT ;
    USE SIGNAL ;
    PORT
      LAYER M5 ;
      RECT 12.720000 0.000000 12.744000 0.084000 ;
    END
  END head_record[313]
  PIN head_record[314]
    DIRECTION INPUT ;
    USE SIGNAL ;
    PORT
      LAYER M5 ;
      RECT 13.008000 0.000000 13.032000 0.084000 ;
    END
  END head_record[314]
  PIN head_record[315]
    DIRECTION INPUT ;
    USE SIGNAL ;
    PORT
      LAYER M5 ;
      RECT 13.296000 0.000000 13.320000 0.084000 ;
    END
  END head_record[315]
  PIN head_record[316]
    DIRECTION INPUT ;
    USE SIGNAL ;
    PORT
      LAYER M5 ;
      RECT 13.584000 0.000000 13.608000 0.084000 ;
    END
  END head_record[316]
  PIN head_record[317]
    DIRECTION INPUT ;
    USE SIGNAL ;
    PORT
      LAYER M5 ;
      RECT 13.872000 0.000000 13.896000 0.084000 ;
    END
  END head_record[317]
  PIN head_record[318]
    DIRECTION INPUT ;
    USE SIGNAL ;
    PORT
      LAYER M5 ;
      RECT 14.160000 0.000000 14.184000 0.084000 ;
    END
  END head_record[318]
  PIN head_record[319]
    DIRECTION INPUT ;
    USE SIGNAL ;
    PORT
      LAYER M5 ;
      RECT 14.400000 0.000000 14.424000 0.084000 ;
    END
  END head_record[319]
  PIN head_record[320]
    DIRECTION INPUT ;
    USE SIGNAL ;
    PORT
      LAYER M5 ;
      RECT 14.688000 0.000000 14.712000 0.084000 ;
    END
  END head_record[320]
  PIN head_record[321]
    DIRECTION INPUT ;
    USE SIGNAL ;
    PORT
      LAYER M5 ;
      RECT 14.976000 0.000000 15.000000 0.084000 ;
    END
  END head_record[321]
  PIN head_record[322]
    DIRECTION INPUT ;
    USE SIGNAL ;
    PORT
      LAYER M5 ;
      RECT 15.264000 0.000000 15.288000 0.084000 ;
    END
  END head_record[322]
  PIN head_record[323]
    DIRECTION INPUT ;
    USE SIGNAL ;
    PORT
      LAYER M5 ;
      RECT 15.552000 0.000000 15.576000 0.084000 ;
    END
  END head_record[323]
  PIN head_record[324]
    DIRECTION INPUT ;
    USE SIGNAL ;
    PORT
      LAYER M5 ;
      RECT 15.840000 0.000000 15.864000 0.084000 ;
    END
  END head_record[324]
  PIN head_record[325]
    DIRECTION INPUT ;
    USE SIGNAL ;
    PORT
      LAYER M5 ;
      RECT 16.128000 0.000000 16.152000 0.084000 ;
    END
  END head_record[325]
  PIN head_record[326]
    DIRECTION INPUT ;
    USE SIGNAL ;
    PORT
      LAYER M5 ;
      RECT 16.368000 0.000000 16.392000 0.084000 ;
    END
  END head_record[326]
  PIN head_record[327]
    DIRECTION INPUT ;
    USE SIGNAL ;
    PORT
      LAYER M5 ;
      RECT 16.656000 0.000000 16.680000 0.084000 ;
    END
  END head_record[327]
  PIN head_record[328]
    DIRECTION INPUT ;
    USE SIGNAL ;
    PORT
      LAYER M5 ;
      RECT 16.944000 0.000000 16.968000 0.084000 ;
    END
  END head_record[328]
  PIN head_record[329]
    DIRECTION INPUT ;
    USE SIGNAL ;
    PORT
      LAYER M5 ;
      RECT 17.232000 0.000000 17.256000 0.084000 ;
    END
  END head_record[329]
  PIN head_record[330]
    DIRECTION INPUT ;
    USE SIGNAL ;
    PORT
      LAYER M5 ;
      RECT 17.520000 0.000000 17.544000 0.084000 ;
    END
  END head_record[330]
  PIN head_record[331]
    DIRECTION INPUT ;
    USE SIGNAL ;
    PORT
      LAYER M5 ;
      RECT 17.808000 0.000000 17.832000 0.084000 ;
    END
  END head_record[331]
  PIN head_record[332]
    DIRECTION INPUT ;
    USE SIGNAL ;
    PORT
      LAYER M5 ;
      RECT 18.096000 0.000000 18.120000 0.084000 ;
    END
  END head_record[332]
  PIN head_record[333]
    DIRECTION INPUT ;
    USE SIGNAL ;
    PORT
      LAYER M5 ;
      RECT 18.336000 0.000000 18.360000 0.084000 ;
    END
  END head_record[333]
  PIN head_record[334]
    DIRECTION INPUT ;
    USE SIGNAL ;
    PORT
      LAYER M5 ;
      RECT 18.624000 0.000000 18.648000 0.084000 ;
    END
  END head_record[334]
  PIN head_record[335]
    DIRECTION INPUT ;
    USE SIGNAL ;
    PORT
      LAYER M5 ;
      RECT 18.912000 0.000000 18.936000 0.084000 ;
    END
  END head_record[335]
  PIN head_record[336]
    DIRECTION INPUT ;
    USE SIGNAL ;
    PORT
      LAYER M5 ;
      RECT 19.200000 0.000000 19.224000 0.084000 ;
    END
  END head_record[336]
  PIN head_record[337]
    DIRECTION INPUT ;
    USE SIGNAL ;
    PORT
      LAYER M5 ;
      RECT 19.488000 0.000000 19.512000 0.084000 ;
    END
  END head_record[337]
  PIN head_record[338]
    DIRECTION INPUT ;
    USE SIGNAL ;
    PORT
      LAYER M5 ;
      RECT 19.776000 0.000000 19.800000 0.084000 ;
    END
  END head_record[338]
  PIN head_record[339]
    DIRECTION INPUT ;
    USE SIGNAL ;
    PORT
      LAYER M5 ;
      RECT 20.064000 0.000000 20.088000 0.084000 ;
    END
  END head_record[339]
  PIN head_record[340]
    DIRECTION INPUT ;
    USE SIGNAL ;
    PORT
      LAYER M5 ;
      RECT 20.304000 0.000000 20.328000 0.084000 ;
    END
  END head_record[340]
  PIN head_record[341]
    DIRECTION INPUT ;
    USE SIGNAL ;
    PORT
      LAYER M5 ;
      RECT 20.592000 0.000000 20.616000 0.084000 ;
    END
  END head_record[341]
  PIN head_record[342]
    DIRECTION INPUT ;
    USE SIGNAL ;
    PORT
      LAYER M5 ;
      RECT 20.880000 0.000000 20.904000 0.084000 ;
    END
  END head_record[342]
  PIN head_record[343]
    DIRECTION INPUT ;
    USE SIGNAL ;
    PORT
      LAYER M5 ;
      RECT 21.168000 0.000000 21.192000 0.084000 ;
    END
  END head_record[343]
  PIN head_record[344]
    DIRECTION INPUT ;
    USE SIGNAL ;
    PORT
      LAYER M5 ;
      RECT 21.456000 0.000000 21.480000 0.084000 ;
    END
  END head_record[344]
  PIN head_record[345]
    DIRECTION INPUT ;
    USE SIGNAL ;
    PORT
      LAYER M5 ;
      RECT 21.744000 0.000000 21.768000 0.084000 ;
    END
  END head_record[345]
  PIN head_record[346]
    DIRECTION INPUT ;
    USE SIGNAL ;
    PORT
      LAYER M5 ;
      RECT 22.032000 0.000000 22.056000 0.084000 ;
    END
  END head_record[346]
  PIN head_record[347]
    DIRECTION INPUT ;
    USE SIGNAL ;
    PORT
      LAYER M5 ;
      RECT 22.272000 0.000000 22.296000 0.084000 ;
    END
  END head_record[347]
  PIN head_record[348]
    DIRECTION INPUT ;
    USE SIGNAL ;
    PORT
      LAYER M5 ;
      RECT 22.560000 0.000000 22.584000 0.084000 ;
    END
  END head_record[348]
  PIN head_record[349]
    DIRECTION INPUT ;
    USE SIGNAL ;
    PORT
      LAYER M5 ;
      RECT 22.848000 0.000000 22.872000 0.084000 ;
    END
  END head_record[349]
  PIN head_record[350]
    DIRECTION INPUT ;
    USE SIGNAL ;
    PORT
      LAYER M5 ;
      RECT 23.136000 0.000000 23.160000 0.084000 ;
    END
  END head_record[350]
  PIN head_record[351]
    DIRECTION INPUT ;
    USE SIGNAL ;
    PORT
      LAYER M5 ;
      RECT 23.424000 0.000000 23.448000 0.084000 ;
    END
  END head_record[351]
  PIN head_record[352]
    DIRECTION INPUT ;
    USE SIGNAL ;
    PORT
      LAYER M5 ;
      RECT 23.712000 0.000000 23.736000 0.084000 ;
    END
  END head_record[352]
  PIN head_record[353]
    DIRECTION INPUT ;
    USE SIGNAL ;
    PORT
      LAYER M5 ;
      RECT 24.000000 0.000000 24.024000 0.084000 ;
    END
  END head_record[353]
  PIN head_record[354]
    DIRECTION INPUT ;
    USE SIGNAL ;
    PORT
      LAYER M5 ;
      RECT 24.240000 0.000000 24.264000 0.084000 ;
    END
  END head_record[354]
  PIN head_record[355]
    DIRECTION INPUT ;
    USE SIGNAL ;
    PORT
      LAYER M5 ;
      RECT 24.528000 0.000000 24.552000 0.084000 ;
    END
  END head_record[355]
  PIN head_record[356]
    DIRECTION INPUT ;
    USE SIGNAL ;
    PORT
      LAYER M5 ;
      RECT 24.816000 0.000000 24.840000 0.084000 ;
    END
  END head_record[356]
  PIN head_record[357]
    DIRECTION INPUT ;
    USE SIGNAL ;
    PORT
      LAYER M5 ;
      RECT 25.104000 0.000000 25.128000 0.084000 ;
    END
  END head_record[357]
  PIN head_record[358]
    DIRECTION INPUT ;
    USE SIGNAL ;
    PORT
      LAYER M5 ;
      RECT 25.392000 0.000000 25.416000 0.084000 ;
    END
  END head_record[358]
  PIN head_record[359]
    DIRECTION INPUT ;
    USE SIGNAL ;
    PORT
      LAYER M5 ;
      RECT 25.680000 0.000000 25.704000 0.084000 ;
    END
  END head_record[359]
  PIN head_record[360]
    DIRECTION INPUT ;
    USE SIGNAL ;
    PORT
      LAYER M5 ;
      RECT 25.968000 0.000000 25.992000 0.084000 ;
    END
  END head_record[360]
  PIN head_record[361]
    DIRECTION INPUT ;
    USE SIGNAL ;
    PORT
      LAYER M5 ;
      RECT 26.208000 0.000000 26.232000 0.084000 ;
    END
  END head_record[361]
  PIN head_record[362]
    DIRECTION INPUT ;
    USE SIGNAL ;
    PORT
      LAYER M5 ;
      RECT 26.496000 0.000000 26.520000 0.084000 ;
    END
  END head_record[362]
  PIN head_record[363]
    DIRECTION INPUT ;
    USE SIGNAL ;
    PORT
      LAYER M5 ;
      RECT 26.784000 0.000000 26.808000 0.084000 ;
    END
  END head_record[363]
  PIN head_record[364]
    DIRECTION INPUT ;
    USE SIGNAL ;
    PORT
      LAYER M5 ;
      RECT 27.072000 0.000000 27.096000 0.084000 ;
    END
  END head_record[364]
  PIN head_record[365]
    DIRECTION INPUT ;
    USE SIGNAL ;
    PORT
      LAYER M5 ;
      RECT 27.360000 0.000000 27.384000 0.084000 ;
    END
  END head_record[365]
  PIN head_record[366]
    DIRECTION INPUT ;
    USE SIGNAL ;
    PORT
      LAYER M5 ;
      RECT 27.648000 0.000000 27.672000 0.084000 ;
    END
  END head_record[366]
  PIN head_record[367]
    DIRECTION INPUT ;
    USE SIGNAL ;
    PORT
      LAYER M5 ;
      RECT 27.888000 0.000000 27.912000 0.084000 ;
    END
  END head_record[367]
  PIN head_record[368]
    DIRECTION INPUT ;
    USE SIGNAL ;
    PORT
      LAYER M5 ;
      RECT 28.176000 0.000000 28.200000 0.084000 ;
    END
  END head_record[368]
  PIN head_record[369]
    DIRECTION INPUT ;
    USE SIGNAL ;
    PORT
      LAYER M5 ;
      RECT 28.464000 0.000000 28.488000 0.084000 ;
    END
  END head_record[369]
  PIN head_record[370]
    DIRECTION INPUT ;
    USE SIGNAL ;
    PORT
      LAYER M5 ;
      RECT 28.752000 0.000000 28.776000 0.084000 ;
    END
  END head_record[370]
  PIN head_record[371]
    DIRECTION INPUT ;
    USE SIGNAL ;
    PORT
      LAYER M5 ;
      RECT 29.040000 0.000000 29.064000 0.084000 ;
    END
  END head_record[371]
  PIN head_record[372]
    DIRECTION INPUT ;
    USE SIGNAL ;
    PORT
      LAYER M5 ;
      RECT 29.328000 0.000000 29.352000 0.084000 ;
    END
  END head_record[372]
  PIN head_record[373]
    DIRECTION INPUT ;
    USE SIGNAL ;
    PORT
      LAYER M5 ;
      RECT 29.616000 0.000000 29.640000 0.084000 ;
    END
  END head_record[373]
  PIN head_record[374]
    DIRECTION INPUT ;
    USE SIGNAL ;
    PORT
      LAYER M5 ;
      RECT 29.856000 0.000000 29.880000 0.084000 ;
    END
  END head_record[374]
  PIN head_record[375]
    DIRECTION INPUT ;
    USE SIGNAL ;
    PORT
      LAYER M5 ;
      RECT 30.144000 0.000000 30.168000 0.084000 ;
    END
  END head_record[375]
  PIN head_record[376]
    DIRECTION INPUT ;
    USE SIGNAL ;
    PORT
      LAYER M5 ;
      RECT 30.432000 0.000000 30.456000 0.084000 ;
    END
  END head_record[376]
  PIN head_record[377]
    DIRECTION INPUT ;
    USE SIGNAL ;
    PORT
      LAYER M5 ;
      RECT 30.720000 0.000000 30.744000 0.084000 ;
    END
  END head_record[377]
  PIN head_record[378]
    DIRECTION INPUT ;
    USE SIGNAL ;
    PORT
      LAYER M5 ;
      RECT 31.008000 0.000000 31.032000 0.084000 ;
    END
  END head_record[378]
  PIN head_record[379]
    DIRECTION INPUT ;
    USE SIGNAL ;
    PORT
      LAYER M5 ;
      RECT 31.296000 0.000000 31.320000 0.084000 ;
    END
  END head_record[379]
  PIN head_record[380]
    DIRECTION INPUT ;
    USE SIGNAL ;
    PORT
      LAYER M5 ;
      RECT 31.584000 0.000000 31.608000 0.084000 ;
    END
  END head_record[380]
  PIN head_record[381]
    DIRECTION INPUT ;
    USE SIGNAL ;
    PORT
      LAYER M5 ;
      RECT 31.824000 0.000000 31.848000 0.084000 ;
    END
  END head_record[381]
  PIN head_record[382]
    DIRECTION INPUT ;
    USE SIGNAL ;
    PORT
      LAYER M5 ;
      RECT 32.112000 0.000000 32.136000 0.084000 ;
    END
  END head_record[382]
  PIN head_record[383]
    DIRECTION INPUT ;
    USE SIGNAL ;
    PORT
      LAYER M5 ;
      RECT 32.400000 0.000000 32.424000 0.084000 ;
    END
  END head_record[383]
  PIN head_record[384]
    DIRECTION INPUT ;
    USE SIGNAL ;
    PORT
      LAYER M5 ;
      RECT 32.688000 0.000000 32.712000 0.084000 ;
    END
  END head_record[384]
  PIN head_record[385]
    DIRECTION INPUT ;
    USE SIGNAL ;
    PORT
      LAYER M5 ;
      RECT 32.976000 0.000000 33.000000 0.084000 ;
    END
  END head_record[385]
  PIN head_record[386]
    DIRECTION INPUT ;
    USE SIGNAL ;
    PORT
      LAYER M5 ;
      RECT 33.264000 0.000000 33.288000 0.084000 ;
    END
  END head_record[386]
  PIN head_record[387]
    DIRECTION INPUT ;
    USE SIGNAL ;
    PORT
      LAYER M5 ;
      RECT 33.552000 0.000000 33.576000 0.084000 ;
    END
  END head_record[387]
  PIN head_record[388]
    DIRECTION INPUT ;
    USE SIGNAL ;
    PORT
      LAYER M5 ;
      RECT 33.792000 0.000000 33.816000 0.084000 ;
    END
  END head_record[388]
  PIN head_record[389]
    DIRECTION INPUT ;
    USE SIGNAL ;
    PORT
      LAYER M5 ;
      RECT 34.080000 0.000000 34.104000 0.084000 ;
    END
  END head_record[389]
  PIN head_record[390]
    DIRECTION INPUT ;
    USE SIGNAL ;
    PORT
      LAYER M5 ;
      RECT 34.368000 0.000000 34.392000 0.084000 ;
    END
  END head_record[390]
  PIN head_record[391]
    DIRECTION INPUT ;
    USE SIGNAL ;
    PORT
      LAYER M5 ;
      RECT 34.656000 0.000000 34.680000 0.084000 ;
    END
  END head_record[391]
  PIN head_record[392]
    DIRECTION INPUT ;
    USE SIGNAL ;
    PORT
      LAYER M5 ;
      RECT 34.944000 0.000000 34.968000 0.084000 ;
    END
  END head_record[392]
  PIN head_record[393]
    DIRECTION INPUT ;
    USE SIGNAL ;
    PORT
      LAYER M5 ;
      RECT 35.232000 0.000000 35.256000 0.084000 ;
    END
  END head_record[393]
  PIN head_record[394]
    DIRECTION INPUT ;
    USE SIGNAL ;
    PORT
      LAYER M5 ;
      RECT 35.520000 0.000000 35.544000 0.084000 ;
    END
  END head_record[394]
  PIN head_record[395]
    DIRECTION INPUT ;
    USE SIGNAL ;
    PORT
      LAYER M5 ;
      RECT 35.760000 0.000000 35.784000 0.084000 ;
    END
  END head_record[395]
  PIN head_record[396]
    DIRECTION INPUT ;
    USE SIGNAL ;
    PORT
      LAYER M5 ;
      RECT 36.048000 0.000000 36.072000 0.084000 ;
    END
  END head_record[396]
  PIN head_record[397]
    DIRECTION INPUT ;
    USE SIGNAL ;
    PORT
      LAYER M5 ;
      RECT 36.336000 0.000000 36.360000 0.084000 ;
    END
  END head_record[397]
  PIN head_record[398]
    DIRECTION INPUT ;
    USE SIGNAL ;
    PORT
      LAYER M5 ;
      RECT 36.624000 0.000000 36.648000 0.084000 ;
    END
  END head_record[398]
  PIN head_record[399]
    DIRECTION INPUT ;
    USE SIGNAL ;
    PORT
      LAYER M5 ;
      RECT 36.912000 0.000000 36.936000 0.084000 ;
    END
  END head_record[399]
  PIN head_record[400]
    DIRECTION INPUT ;
    USE SIGNAL ;
    PORT
      LAYER M5 ;
      RECT 37.200000 0.000000 37.224000 0.084000 ;
    END
  END head_record[400]
  PIN head_record[401]
    DIRECTION INPUT ;
    USE SIGNAL ;
    PORT
      LAYER M5 ;
      RECT 37.488000 0.000000 37.512000 0.084000 ;
    END
  END head_record[401]
  PIN head_record[402]
    DIRECTION INPUT ;
    USE SIGNAL ;
    PORT
      LAYER M5 ;
      RECT 37.728000 0.000000 37.752000 0.084000 ;
    END
  END head_record[402]
  PIN head_record[403]
    DIRECTION INPUT ;
    USE SIGNAL ;
    PORT
      LAYER M5 ;
      RECT 38.016000 0.000000 38.040000 0.084000 ;
    END
  END head_record[403]
  PIN head_record[404]
    DIRECTION INPUT ;
    USE SIGNAL ;
    PORT
      LAYER M5 ;
      RECT 38.304000 0.000000 38.328000 0.084000 ;
    END
  END head_record[404]
  PIN head_record[405]
    DIRECTION INPUT ;
    USE SIGNAL ;
    PORT
      LAYER M5 ;
      RECT 38.592000 0.000000 38.616000 0.084000 ;
    END
  END head_record[405]
  PIN head_record[406]
    DIRECTION INPUT ;
    USE SIGNAL ;
    PORT
      LAYER M5 ;
      RECT 38.880000 0.000000 38.904000 0.084000 ;
    END
  END head_record[406]
  PIN head_record[407]
    DIRECTION INPUT ;
    USE SIGNAL ;
    PORT
      LAYER M5 ;
      RECT 39.168000 0.000000 39.192000 0.084000 ;
    END
  END head_record[407]
  PIN head_record[408]
    DIRECTION INPUT ;
    USE SIGNAL ;
    PORT
      LAYER M5 ;
      RECT 39.456000 0.000000 39.480000 0.084000 ;
    END
  END head_record[408]
  PIN head_record[409]
    DIRECTION INPUT ;
    USE SIGNAL ;
    PORT
      LAYER M5 ;
      RECT 39.696000 0.000000 39.720000 0.084000 ;
    END
  END head_record[409]
  PIN head_record[410]
    DIRECTION INPUT ;
    USE SIGNAL ;
    PORT
      LAYER M5 ;
      RECT 39.984000 0.000000 40.008000 0.084000 ;
    END
  END head_record[410]
  PIN head_record[411]
    DIRECTION INPUT ;
    USE SIGNAL ;
    PORT
      LAYER M5 ;
      RECT 40.272000 0.000000 40.296000 0.084000 ;
    END
  END head_record[411]
  PIN head_record[412]
    DIRECTION INPUT ;
    USE SIGNAL ;
    PORT
      LAYER M5 ;
      RECT 40.560000 0.000000 40.584000 0.084000 ;
    END
  END head_record[412]
  PIN head_record[413]
    DIRECTION INPUT ;
    USE SIGNAL ;
    PORT
      LAYER M5 ;
      RECT 40.848000 0.000000 40.872000 0.084000 ;
    END
  END head_record[413]
  PIN head_record[414]
    DIRECTION INPUT ;
    USE SIGNAL ;
    PORT
      LAYER M4 ;
      RECT 43.116000 2.304000 43.200000 2.328000 ;
    END
  END head_record[414]
  PIN head_record[415]
    DIRECTION INPUT ;
    USE SIGNAL ;
    PORT
      LAYER M4 ;
      RECT 43.116000 2.496000 43.200000 2.520000 ;
    END
  END head_record[415]
  PIN head_record[416]
    DIRECTION INPUT ;
    USE SIGNAL ;
    PORT
      LAYER M4 ;
      RECT 43.116000 2.688000 43.200000 2.712000 ;
    END
  END head_record[416]
  PIN head_record[417]
    DIRECTION INPUT ;
    USE SIGNAL ;
    PORT
      LAYER M4 ;
      RECT 43.116000 2.880000 43.200000 2.904000 ;
    END
  END head_record[417]
  PIN head_record[418]
    DIRECTION INPUT ;
    USE SIGNAL ;
    PORT
      LAYER M4 ;
      RECT 43.116000 3.072000 43.200000 3.096000 ;
    END
  END head_record[418]
  PIN head_record[419]
    DIRECTION INPUT ;
    USE SIGNAL ;
    PORT
      LAYER M4 ;
      RECT 43.116000 3.264000 43.200000 3.288000 ;
    END
  END head_record[419]
  PIN head_record[420]
    DIRECTION INPUT ;
    USE SIGNAL ;
    PORT
      LAYER M4 ;
      RECT 43.116000 3.456000 43.200000 3.480000 ;
    END
  END head_record[420]
  PIN head_record[421]
    DIRECTION INPUT ;
    USE SIGNAL ;
    PORT
      LAYER M4 ;
      RECT 43.116000 3.648000 43.200000 3.672000 ;
    END
  END head_record[421]
  PIN head_record[422]
    DIRECTION INPUT ;
    USE SIGNAL ;
    PORT
      LAYER M4 ;
      RECT 43.116000 3.840000 43.200000 3.864000 ;
    END
  END head_record[422]
  PIN head_record[423]
    DIRECTION INPUT ;
    USE SIGNAL ;
    PORT
      LAYER M4 ;
      RECT 43.116000 4.032000 43.200000 4.056000 ;
    END
  END head_record[423]
  PIN head_record[424]
    DIRECTION INPUT ;
    USE SIGNAL ;
    PORT
      LAYER M4 ;
      RECT 43.116000 4.224000 43.200000 4.248000 ;
    END
  END head_record[424]
  PIN head_record[425]
    DIRECTION INPUT ;
    USE SIGNAL ;
    PORT
      LAYER M4 ;
      RECT 43.116000 4.416000 43.200000 4.440000 ;
    END
  END head_record[425]
  PIN head_record[426]
    DIRECTION INPUT ;
    USE SIGNAL ;
    PORT
      LAYER M4 ;
      RECT 43.116000 4.608000 43.200000 4.632000 ;
    END
  END head_record[426]
  PIN head_record[427]
    DIRECTION INPUT ;
    USE SIGNAL ;
    PORT
      LAYER M4 ;
      RECT 43.116000 4.800000 43.200000 4.824000 ;
    END
  END head_record[427]
  PIN head_record[428]
    DIRECTION INPUT ;
    USE SIGNAL ;
    PORT
      LAYER M4 ;
      RECT 43.116000 4.992000 43.200000 5.016000 ;
    END
  END head_record[428]
  PIN head_record[429]
    DIRECTION INPUT ;
    USE SIGNAL ;
    PORT
      LAYER M4 ;
      RECT 43.116000 5.184000 43.200000 5.208000 ;
    END
  END head_record[429]
  PIN head_record[430]
    DIRECTION INPUT ;
    USE SIGNAL ;
    PORT
      LAYER M4 ;
      RECT 43.116000 5.376000 43.200000 5.400000 ;
    END
  END head_record[430]
  PIN head_record[431]
    DIRECTION INPUT ;
    USE SIGNAL ;
    PORT
      LAYER M4 ;
      RECT 43.116000 5.568000 43.200000 5.592000 ;
    END
  END head_record[431]
  PIN head_record[432]
    DIRECTION INPUT ;
    USE SIGNAL ;
    PORT
      LAYER M4 ;
      RECT 43.116000 5.760000 43.200000 5.784000 ;
    END
  END head_record[432]
  PIN head_record[433]
    DIRECTION INPUT ;
    USE SIGNAL ;
    PORT
      LAYER M4 ;
      RECT 43.116000 6.000000 43.200000 6.024000 ;
    END
  END head_record[433]
  PIN head_record[434]
    DIRECTION INPUT ;
    USE SIGNAL ;
    PORT
      LAYER M4 ;
      RECT 43.116000 6.192000 43.200000 6.216000 ;
    END
  END head_record[434]
  PIN head_record[435]
    DIRECTION INPUT ;
    USE SIGNAL ;
    PORT
      LAYER M4 ;
      RECT 43.116000 6.384000 43.200000 6.408000 ;
    END
  END head_record[435]
  PIN head_record[436]
    DIRECTION INPUT ;
    USE SIGNAL ;
    PORT
      LAYER M4 ;
      RECT 43.116000 6.576000 43.200000 6.600000 ;
    END
  END head_record[436]
  PIN head_record[437]
    DIRECTION INPUT ;
    USE SIGNAL ;
    PORT
      LAYER M4 ;
      RECT 43.116000 6.768000 43.200000 6.792000 ;
    END
  END head_record[437]
  PIN head_record[438]
    DIRECTION INPUT ;
    USE SIGNAL ;
    PORT
      LAYER M4 ;
      RECT 43.116000 6.960000 43.200000 6.984000 ;
    END
  END head_record[438]
  PIN head_record[439]
    DIRECTION INPUT ;
    USE SIGNAL ;
    PORT
      LAYER M4 ;
      RECT 43.116000 7.152000 43.200000 7.176000 ;
    END
  END head_record[439]
  PIN head_record[440]
    DIRECTION INPUT ;
    USE SIGNAL ;
    PORT
      LAYER M4 ;
      RECT 43.116000 7.344000 43.200000 7.368000 ;
    END
  END head_record[440]
  PIN head_record[441]
    DIRECTION INPUT ;
    USE SIGNAL ;
    PORT
      LAYER M4 ;
      RECT 43.116000 7.536000 43.200000 7.560000 ;
    END
  END head_record[441]
  PIN head_record[442]
    DIRECTION INPUT ;
    USE SIGNAL ;
    PORT
      LAYER M4 ;
      RECT 43.116000 7.728000 43.200000 7.752000 ;
    END
  END head_record[442]
  PIN head_record[443]
    DIRECTION INPUT ;
    USE SIGNAL ;
    PORT
      LAYER M4 ;
      RECT 43.116000 7.920000 43.200000 7.944000 ;
    END
  END head_record[443]
  PIN head_record[444]
    DIRECTION INPUT ;
    USE SIGNAL ;
    PORT
      LAYER M4 ;
      RECT 43.116000 8.112000 43.200000 8.136000 ;
    END
  END head_record[444]
  PIN head_record[445]
    DIRECTION INPUT ;
    USE SIGNAL ;
    PORT
      LAYER M4 ;
      RECT 43.116000 8.304000 43.200000 8.328000 ;
    END
  END head_record[445]
  PIN head_record[446]
    DIRECTION INPUT ;
    USE SIGNAL ;
    PORT
      LAYER M4 ;
      RECT 43.116000 8.496000 43.200000 8.520000 ;
    END
  END head_record[446]
  PIN head_record[447]
    DIRECTION INPUT ;
    USE SIGNAL ;
    PORT
      LAYER M4 ;
      RECT 43.116000 8.688000 43.200000 8.712000 ;
    END
  END head_record[447]
  PIN head_record[448]
    DIRECTION INPUT ;
    USE SIGNAL ;
    PORT
      LAYER M4 ;
      RECT 43.116000 8.880000 43.200000 8.904000 ;
    END
  END head_record[448]
  PIN head_record[449]
    DIRECTION INPUT ;
    USE SIGNAL ;
    PORT
      LAYER M4 ;
      RECT 43.116000 9.072000 43.200000 9.096000 ;
    END
  END head_record[449]
  PIN head_record[450]
    DIRECTION INPUT ;
    USE SIGNAL ;
    PORT
      LAYER M4 ;
      RECT 43.116000 9.264000 43.200000 9.288000 ;
    END
  END head_record[450]
  PIN head_record[451]
    DIRECTION INPUT ;
    USE SIGNAL ;
    PORT
      LAYER M4 ;
      RECT 43.116000 9.456000 43.200000 9.480000 ;
    END
  END head_record[451]
  PIN head_record[452]
    DIRECTION INPUT ;
    USE SIGNAL ;
    PORT
      LAYER M4 ;
      RECT 43.116000 9.648000 43.200000 9.672000 ;
    END
  END head_record[452]
  PIN head_record[453]
    DIRECTION INPUT ;
    USE SIGNAL ;
    PORT
      LAYER M4 ;
      RECT 43.116000 9.840000 43.200000 9.864000 ;
    END
  END head_record[453]
  PIN head_record[454]
    DIRECTION INPUT ;
    USE SIGNAL ;
    PORT
      LAYER M4 ;
      RECT 43.116000 10.032000 43.200000 10.056000 ;
    END
  END head_record[454]
  PIN head_record[455]
    DIRECTION INPUT ;
    USE SIGNAL ;
    PORT
      LAYER M4 ;
      RECT 43.116000 10.224000 43.200000 10.248000 ;
    END
  END head_record[455]
  PIN head_record[456]
    DIRECTION INPUT ;
    USE SIGNAL ;
    PORT
      LAYER M4 ;
      RECT 43.116000 10.416000 43.200000 10.440000 ;
    END
  END head_record[456]
  PIN head_record[457]
    DIRECTION INPUT ;
    USE SIGNAL ;
    PORT
      LAYER M4 ;
      RECT 43.116000 10.608000 43.200000 10.632000 ;
    END
  END head_record[457]
  PIN head_record[458]
    DIRECTION INPUT ;
    USE SIGNAL ;
    PORT
      LAYER M4 ;
      RECT 43.116000 10.848000 43.200000 10.872000 ;
    END
  END head_record[458]
  PIN head_record[459]
    DIRECTION INPUT ;
    USE SIGNAL ;
    PORT
      LAYER M4 ;
      RECT 43.116000 11.040000 43.200000 11.064000 ;
    END
  END head_record[459]
  PIN head_record[460]
    DIRECTION INPUT ;
    USE SIGNAL ;
    PORT
      LAYER M4 ;
      RECT 43.116000 11.232000 43.200000 11.256000 ;
    END
  END head_record[460]
  PIN head_record[461]
    DIRECTION INPUT ;
    USE SIGNAL ;
    PORT
      LAYER M4 ;
      RECT 43.116000 11.424000 43.200000 11.448000 ;
    END
  END head_record[461]
  PIN head_record[462]
    DIRECTION INPUT ;
    USE SIGNAL ;
    PORT
      LAYER M4 ;
      RECT 43.116000 11.616000 43.200000 11.640000 ;
    END
  END head_record[462]
  PIN head_record[463]
    DIRECTION INPUT ;
    USE SIGNAL ;
    PORT
      LAYER M4 ;
      RECT 43.116000 11.808000 43.200000 11.832000 ;
    END
  END head_record[463]
  PIN head_record[464]
    DIRECTION INPUT ;
    USE SIGNAL ;
    PORT
      LAYER M4 ;
      RECT 43.116000 12.000000 43.200000 12.024000 ;
    END
  END head_record[464]
  PIN head_record[465]
    DIRECTION INPUT ;
    USE SIGNAL ;
    PORT
      LAYER M4 ;
      RECT 43.116000 12.192000 43.200000 12.216000 ;
    END
  END head_record[465]
  PIN head_record[466]
    DIRECTION INPUT ;
    USE SIGNAL ;
    PORT
      LAYER M4 ;
      RECT 43.116000 12.384000 43.200000 12.408000 ;
    END
  END head_record[466]
  PIN head_record[467]
    DIRECTION INPUT ;
    USE SIGNAL ;
    PORT
      LAYER M4 ;
      RECT 43.116000 12.576000 43.200000 12.600000 ;
    END
  END head_record[467]
  PIN head_record[468]
    DIRECTION INPUT ;
    USE SIGNAL ;
    PORT
      LAYER M4 ;
      RECT 43.116000 12.768000 43.200000 12.792000 ;
    END
  END head_record[468]
  PIN head_record[469]
    DIRECTION INPUT ;
    USE SIGNAL ;
    PORT
      LAYER M4 ;
      RECT 43.116000 12.960000 43.200000 12.984000 ;
    END
  END head_record[469]
  PIN head_record[470]
    DIRECTION INPUT ;
    USE SIGNAL ;
    PORT
      LAYER M4 ;
      RECT 43.116000 13.152000 43.200000 13.176000 ;
    END
  END head_record[470]
  PIN head_record[471]
    DIRECTION INPUT ;
    USE SIGNAL ;
    PORT
      LAYER M4 ;
      RECT 43.116000 13.344000 43.200000 13.368000 ;
    END
  END head_record[471]
  PIN head_record[472]
    DIRECTION INPUT ;
    USE SIGNAL ;
    PORT
      LAYER M4 ;
      RECT 43.116000 13.536000 43.200000 13.560000 ;
    END
  END head_record[472]
  PIN head_record[473]
    DIRECTION INPUT ;
    USE SIGNAL ;
    PORT
      LAYER M4 ;
      RECT 43.116000 13.728000 43.200000 13.752000 ;
    END
  END head_record[473]
  PIN head_record[474]
    DIRECTION INPUT ;
    USE SIGNAL ;
    PORT
      LAYER M4 ;
      RECT 43.116000 13.920000 43.200000 13.944000 ;
    END
  END head_record[474]
  PIN head_record[475]
    DIRECTION INPUT ;
    USE SIGNAL ;
    PORT
      LAYER M4 ;
      RECT 43.116000 14.112000 43.200000 14.136000 ;
    END
  END head_record[475]
  PIN head_record[476]
    DIRECTION INPUT ;
    USE SIGNAL ;
    PORT
      LAYER M4 ;
      RECT 43.116000 14.304000 43.200000 14.328000 ;
    END
  END head_record[476]
  PIN head_record[477]
    DIRECTION INPUT ;
    USE SIGNAL ;
    PORT
      LAYER M4 ;
      RECT 43.116000 14.496000 43.200000 14.520000 ;
    END
  END head_record[477]
  PIN head_record[478]
    DIRECTION INPUT ;
    USE SIGNAL ;
    PORT
      LAYER M4 ;
      RECT 43.116000 14.688000 43.200000 14.712000 ;
    END
  END head_record[478]
  PIN head_record[479]
    DIRECTION INPUT ;
    USE SIGNAL ;
    PORT
      LAYER M4 ;
      RECT 43.116000 14.880000 43.200000 14.904000 ;
    END
  END head_record[479]
  PIN head_record[480]
    DIRECTION INPUT ;
    USE SIGNAL ;
    PORT
      LAYER M4 ;
      RECT 43.116000 15.072000 43.200000 15.096000 ;
    END
  END head_record[480]
  PIN head_record[481]
    DIRECTION INPUT ;
    USE SIGNAL ;
    PORT
      LAYER M4 ;
      RECT 43.116000 15.264000 43.200000 15.288000 ;
    END
  END head_record[481]
  PIN head_record[482]
    DIRECTION INPUT ;
    USE SIGNAL ;
    PORT
      LAYER M4 ;
      RECT 43.116000 15.456000 43.200000 15.480000 ;
    END
  END head_record[482]
  PIN head_record[483]
    DIRECTION INPUT ;
    USE SIGNAL ;
    PORT
      LAYER M4 ;
      RECT 43.116000 15.696000 43.200000 15.720000 ;
    END
  END head_record[483]
  PIN head_record[484]
    DIRECTION INPUT ;
    USE SIGNAL ;
    PORT
      LAYER M4 ;
      RECT 43.116000 15.888000 43.200000 15.912000 ;
    END
  END head_record[484]
  PIN head_record[485]
    DIRECTION INPUT ;
    USE SIGNAL ;
    PORT
      LAYER M4 ;
      RECT 43.116000 16.080000 43.200000 16.104000 ;
    END
  END head_record[485]
  PIN head_record[486]
    DIRECTION INPUT ;
    USE SIGNAL ;
    PORT
      LAYER M4 ;
      RECT 43.116000 16.272000 43.200000 16.296000 ;
    END
  END head_record[486]
  PIN head_record[487]
    DIRECTION INPUT ;
    USE SIGNAL ;
    PORT
      LAYER M4 ;
      RECT 43.116000 16.464000 43.200000 16.488000 ;
    END
  END head_record[487]
  PIN head_record[488]
    DIRECTION INPUT ;
    USE SIGNAL ;
    PORT
      LAYER M4 ;
      RECT 43.116000 16.656000 43.200000 16.680000 ;
    END
  END head_record[488]
  PIN head_record[489]
    DIRECTION INPUT ;
    USE SIGNAL ;
    PORT
      LAYER M4 ;
      RECT 43.116000 16.848000 43.200000 16.872000 ;
    END
  END head_record[489]
  PIN head_record[490]
    DIRECTION INPUT ;
    USE SIGNAL ;
    PORT
      LAYER M4 ;
      RECT 43.116000 17.040000 43.200000 17.064000 ;
    END
  END head_record[490]
  PIN head_record[491]
    DIRECTION INPUT ;
    USE SIGNAL ;
    PORT
      LAYER M4 ;
      RECT 43.116000 17.232000 43.200000 17.256000 ;
    END
  END head_record[491]
  PIN head_record[492]
    DIRECTION INPUT ;
    USE SIGNAL ;
    PORT
      LAYER M4 ;
      RECT 43.116000 17.424000 43.200000 17.448000 ;
    END
  END head_record[492]
  PIN head_record[493]
    DIRECTION INPUT ;
    USE SIGNAL ;
    PORT
      LAYER M4 ;
      RECT 43.116000 17.616000 43.200000 17.640000 ;
    END
  END head_record[493]
  PIN head_record[494]
    DIRECTION INPUT ;
    USE SIGNAL ;
    PORT
      LAYER M4 ;
      RECT 43.116000 17.808000 43.200000 17.832000 ;
    END
  END head_record[494]
  PIN head_record[495]
    DIRECTION INPUT ;
    USE SIGNAL ;
    PORT
      LAYER M4 ;
      RECT 43.116000 18.000000 43.200000 18.024000 ;
    END
  END head_record[495]
  PIN head_record[496]
    DIRECTION INPUT ;
    USE SIGNAL ;
    PORT
      LAYER M4 ;
      RECT 43.116000 18.192000 43.200000 18.216000 ;
    END
  END head_record[496]
  PIN head_record[497]
    DIRECTION INPUT ;
    USE SIGNAL ;
    PORT
      LAYER M4 ;
      RECT 43.116000 18.384000 43.200000 18.408000 ;
    END
  END head_record[497]
  PIN head_record[498]
    DIRECTION INPUT ;
    USE SIGNAL ;
    PORT
      LAYER M4 ;
      RECT 43.116000 18.576000 43.200000 18.600000 ;
    END
  END head_record[498]
  PIN head_record[499]
    DIRECTION INPUT ;
    USE SIGNAL ;
    PORT
      LAYER M4 ;
      RECT 43.116000 18.768000 43.200000 18.792000 ;
    END
  END head_record[499]
  PIN head_record[500]
    DIRECTION INPUT ;
    USE SIGNAL ;
    PORT
      LAYER M4 ;
      RECT 43.116000 18.960000 43.200000 18.984000 ;
    END
  END head_record[500]
  PIN head_record[501]
    DIRECTION INPUT ;
    USE SIGNAL ;
    PORT
      LAYER M4 ;
      RECT 43.116000 19.152000 43.200000 19.176000 ;
    END
  END head_record[501]
  PIN head_record[502]
    DIRECTION INPUT ;
    USE SIGNAL ;
    PORT
      LAYER M4 ;
      RECT 43.116000 19.344000 43.200000 19.368000 ;
    END
  END head_record[502]
  PIN head_record[503]
    DIRECTION INPUT ;
    USE SIGNAL ;
    PORT
      LAYER M4 ;
      RECT 43.116000 19.536000 43.200000 19.560000 ;
    END
  END head_record[503]
  PIN head_record[504]
    DIRECTION INPUT ;
    USE SIGNAL ;
    PORT
      LAYER M4 ;
      RECT 43.116000 19.728000 43.200000 19.752000 ;
    END
  END head_record[504]
  PIN head_record[505]
    DIRECTION INPUT ;
    USE SIGNAL ;
    PORT
      LAYER M4 ;
      RECT 43.116000 19.920000 43.200000 19.944000 ;
    END
  END head_record[505]
  PIN head_record[506]
    DIRECTION INPUT ;
    USE SIGNAL ;
    PORT
      LAYER M4 ;
      RECT 43.116000 20.112000 43.200000 20.136000 ;
    END
  END head_record[506]
  PIN head_record[507]
    DIRECTION INPUT ;
    USE SIGNAL ;
    PORT
      LAYER M4 ;
      RECT 43.116000 20.304000 43.200000 20.328000 ;
    END
  END head_record[507]
  PIN head_record[508]
    DIRECTION INPUT ;
    USE SIGNAL ;
    PORT
      LAYER M4 ;
      RECT 43.116000 20.544000 43.200000 20.568000 ;
    END
  END head_record[508]
  PIN head_record[509]
    DIRECTION INPUT ;
    USE SIGNAL ;
    PORT
      LAYER M4 ;
      RECT 43.116000 20.736000 43.200000 20.760000 ;
    END
  END head_record[509]
  PIN head_record[510]
    DIRECTION INPUT ;
    USE SIGNAL ;
    PORT
      LAYER M4 ;
      RECT 43.116000 20.928000 43.200000 20.952000 ;
    END
  END head_record[510]
  PIN head_record[511]
    DIRECTION INPUT ;
    USE SIGNAL ;
    PORT
      LAYER M4 ;
      RECT 43.116000 21.120000 43.200000 21.144000 ;
    END
  END head_record[511]
  PIN head_record[512]
    DIRECTION INPUT ;
    USE SIGNAL ;
    PORT
      LAYER M4 ;
      RECT 43.116000 21.312000 43.200000 21.336000 ;
    END
  END head_record[512]
  PIN head_record[513]
    DIRECTION INPUT ;
    USE SIGNAL ;
    PORT
      LAYER M4 ;
      RECT 43.116000 21.504000 43.200000 21.528000 ;
    END
  END head_record[513]
  PIN head_record[514]
    DIRECTION INPUT ;
    USE SIGNAL ;
    PORT
      LAYER M4 ;
      RECT 43.116000 21.696000 43.200000 21.720000 ;
    END
  END head_record[514]
  PIN head_record[515]
    DIRECTION INPUT ;
    USE SIGNAL ;
    PORT
      LAYER M4 ;
      RECT 43.116000 21.888000 43.200000 21.912000 ;
    END
  END head_record[515]
  PIN head_record[516]
    DIRECTION INPUT ;
    USE SIGNAL ;
    PORT
      LAYER M4 ;
      RECT 43.116000 22.080000 43.200000 22.104000 ;
    END
  END head_record[516]
  PIN head_record[517]
    DIRECTION INPUT ;
    USE SIGNAL ;
    PORT
      LAYER M4 ;
      RECT 43.116000 22.272000 43.200000 22.296000 ;
    END
  END head_record[517]
  PIN head_record[518]
    DIRECTION INPUT ;
    USE SIGNAL ;
    PORT
      LAYER M4 ;
      RECT 43.116000 22.464000 43.200000 22.488000 ;
    END
  END head_record[518]
  PIN head_record[519]
    DIRECTION INPUT ;
    USE SIGNAL ;
    PORT
      LAYER M4 ;
      RECT 43.116000 22.656000 43.200000 22.680000 ;
    END
  END head_record[519]
  PIN head_record[520]
    DIRECTION INPUT ;
    USE SIGNAL ;
    PORT
      LAYER M4 ;
      RECT 43.116000 22.848000 43.200000 22.872000 ;
    END
  END head_record[520]
  PIN head_record[521]
    DIRECTION INPUT ;
    USE SIGNAL ;
    PORT
      LAYER M4 ;
      RECT 43.116000 23.040000 43.200000 23.064000 ;
    END
  END head_record[521]
  PIN head_record[522]
    DIRECTION INPUT ;
    USE SIGNAL ;
    PORT
      LAYER M4 ;
      RECT 43.116000 23.232000 43.200000 23.256000 ;
    END
  END head_record[522]
  PIN head_record[523]
    DIRECTION INPUT ;
    USE SIGNAL ;
    PORT
      LAYER M4 ;
      RECT 43.116000 23.424000 43.200000 23.448000 ;
    END
  END head_record[523]
  PIN head_record[524]
    DIRECTION INPUT ;
    USE SIGNAL ;
    PORT
      LAYER M4 ;
      RECT 43.116000 23.616000 43.200000 23.640000 ;
    END
  END head_record[524]
  PIN head_record[525]
    DIRECTION INPUT ;
    USE SIGNAL ;
    PORT
      LAYER M4 ;
      RECT 43.116000 23.808000 43.200000 23.832000 ;
    END
  END head_record[525]
  PIN head_record[526]
    DIRECTION INPUT ;
    USE SIGNAL ;
    PORT
      LAYER M4 ;
      RECT 43.116000 24.000000 43.200000 24.024000 ;
    END
  END head_record[526]
  PIN head_record[527]
    DIRECTION INPUT ;
    USE SIGNAL ;
    PORT
      LAYER M4 ;
      RECT 43.116000 24.192000 43.200000 24.216000 ;
    END
  END head_record[527]
  PIN head_record[528]
    DIRECTION INPUT ;
    USE SIGNAL ;
    PORT
      LAYER M4 ;
      RECT 43.116000 24.384000 43.200000 24.408000 ;
    END
  END head_record[528]
  PIN head_record[529]
    DIRECTION INPUT ;
    USE SIGNAL ;
    PORT
      LAYER M4 ;
      RECT 43.116000 24.576000 43.200000 24.600000 ;
    END
  END head_record[529]
  PIN head_record[530]
    DIRECTION INPUT ;
    USE SIGNAL ;
    PORT
      LAYER M4 ;
      RECT 43.116000 24.768000 43.200000 24.792000 ;
    END
  END head_record[530]
  PIN head_record[531]
    DIRECTION INPUT ;
    USE SIGNAL ;
    PORT
      LAYER M4 ;
      RECT 43.116000 24.960000 43.200000 24.984000 ;
    END
  END head_record[531]
  PIN head_record[532]
    DIRECTION INPUT ;
    USE SIGNAL ;
    PORT
      LAYER M4 ;
      RECT 43.116000 25.152000 43.200000 25.176000 ;
    END
  END head_record[532]
  PIN head_record[533]
    DIRECTION INPUT ;
    USE SIGNAL ;
    PORT
      LAYER M4 ;
      RECT 43.116000 25.392000 43.200000 25.416000 ;
    END
  END head_record[533]
  PIN head_record[534]
    DIRECTION INPUT ;
    USE SIGNAL ;
    PORT
      LAYER M4 ;
      RECT 43.116000 25.584000 43.200000 25.608000 ;
    END
  END head_record[534]
  PIN head_record[535]
    DIRECTION INPUT ;
    USE SIGNAL ;
    PORT
      LAYER M4 ;
      RECT 43.116000 25.776000 43.200000 25.800000 ;
    END
  END head_record[535]
  PIN head_record[536]
    DIRECTION INPUT ;
    USE SIGNAL ;
    PORT
      LAYER M4 ;
      RECT 43.116000 25.968000 43.200000 25.992000 ;
    END
  END head_record[536]
  PIN head_record[537]
    DIRECTION INPUT ;
    USE SIGNAL ;
    PORT
      LAYER M4 ;
      RECT 43.116000 26.160000 43.200000 26.184000 ;
    END
  END head_record[537]
  PIN head_record[538]
    DIRECTION INPUT ;
    USE SIGNAL ;
    PORT
      LAYER M4 ;
      RECT 43.116000 26.352000 43.200000 26.376000 ;
    END
  END head_record[538]
  PIN head_record[539]
    DIRECTION INPUT ;
    USE SIGNAL ;
    PORT
      LAYER M4 ;
      RECT 43.116000 26.544000 43.200000 26.568000 ;
    END
  END head_record[539]
  PIN head_record[540]
    DIRECTION INPUT ;
    USE SIGNAL ;
    PORT
      LAYER M4 ;
      RECT 43.116000 26.736000 43.200000 26.760000 ;
    END
  END head_record[540]
  PIN head_record[541]
    DIRECTION INPUT ;
    USE SIGNAL ;
    PORT
      LAYER M4 ;
      RECT 43.116000 26.928000 43.200000 26.952000 ;
    END
  END head_record[541]
  PIN head_record[542]
    DIRECTION INPUT ;
    USE SIGNAL ;
    PORT
      LAYER M4 ;
      RECT 43.116000 27.120000 43.200000 27.144000 ;
    END
  END head_record[542]
  PIN head_record[543]
    DIRECTION INPUT ;
    USE SIGNAL ;
    PORT
      LAYER M4 ;
      RECT 43.116000 27.312000 43.200000 27.336000 ;
    END
  END head_record[543]
  PIN head_record[544]
    DIRECTION INPUT ;
    USE SIGNAL ;
    PORT
      LAYER M4 ;
      RECT 43.116000 27.504000 43.200000 27.528000 ;
    END
  END head_record[544]
  PIN head_record[545]
    DIRECTION INPUT ;
    USE SIGNAL ;
    PORT
      LAYER M4 ;
      RECT 43.116000 27.696000 43.200000 27.720000 ;
    END
  END head_record[545]
  PIN head_record[546]
    DIRECTION INPUT ;
    USE SIGNAL ;
    PORT
      LAYER M4 ;
      RECT 43.116000 27.888000 43.200000 27.912000 ;
    END
  END head_record[546]
  PIN head_record[547]
    DIRECTION INPUT ;
    USE SIGNAL ;
    PORT
      LAYER M4 ;
      RECT 43.116000 28.080000 43.200000 28.104000 ;
    END
  END head_record[547]
  PIN head_record[548]
    DIRECTION INPUT ;
    USE SIGNAL ;
    PORT
      LAYER M4 ;
      RECT 43.116000 28.272000 43.200000 28.296000 ;
    END
  END head_record[548]
  PIN head_record[549]
    DIRECTION INPUT ;
    USE SIGNAL ;
    PORT
      LAYER M4 ;
      RECT 43.116000 28.464000 43.200000 28.488000 ;
    END
  END head_record[549]
  PIN head_record[550]
    DIRECTION INPUT ;
    USE SIGNAL ;
    PORT
      LAYER M4 ;
      RECT 43.116000 28.656000 43.200000 28.680000 ;
    END
  END head_record[550]
  PIN head_record[551]
    DIRECTION INPUT ;
    USE SIGNAL ;
    PORT
      LAYER M4 ;
      RECT 43.116000 28.848000 43.200000 28.872000 ;
    END
  END head_record[551]
  PIN compiled_identity[0]
    DIRECTION OUTPUT ;
    USE SIGNAL ;
    PORT
      LAYER M4 ;
      RECT 43.116000 29.040000 43.200000 29.064000 ;
    END
  END compiled_identity[0]
  PIN compiled_identity[1]
    DIRECTION OUTPUT ;
    USE SIGNAL ;
    PORT
      LAYER M4 ;
      RECT 43.116000 29.232000 43.200000 29.256000 ;
    END
  END compiled_identity[1]
  PIN compiled_identity[2]
    DIRECTION OUTPUT ;
    USE SIGNAL ;
    PORT
      LAYER M4 ;
      RECT 43.116000 29.424000 43.200000 29.448000 ;
    END
  END compiled_identity[2]
  PIN compiled_identity[3]
    DIRECTION OUTPUT ;
    USE SIGNAL ;
    PORT
      LAYER M4 ;
      RECT 43.116000 29.616000 43.200000 29.640000 ;
    END
  END compiled_identity[3]
  PIN compiled_identity[4]
    DIRECTION OUTPUT ;
    USE SIGNAL ;
    PORT
      LAYER M4 ;
      RECT 43.116000 29.808000 43.200000 29.832000 ;
    END
  END compiled_identity[4]
  PIN compiled_identity[5]
    DIRECTION OUTPUT ;
    USE SIGNAL ;
    PORT
      LAYER M4 ;
      RECT 43.116000 30.000000 43.200000 30.024000 ;
    END
  END compiled_identity[5]
  PIN compiled_identity[6]
    DIRECTION OUTPUT ;
    USE SIGNAL ;
    PORT
      LAYER M4 ;
      RECT 43.116000 30.240000 43.200000 30.264000 ;
    END
  END compiled_identity[6]
  PIN compiled_identity[7]
    DIRECTION OUTPUT ;
    USE SIGNAL ;
    PORT
      LAYER M4 ;
      RECT 43.116000 30.432000 43.200000 30.456000 ;
    END
  END compiled_identity[7]
  PIN compiled_identity[8]
    DIRECTION OUTPUT ;
    USE SIGNAL ;
    PORT
      LAYER M4 ;
      RECT 43.116000 30.624000 43.200000 30.648000 ;
    END
  END compiled_identity[8]
  PIN compiled_identity[9]
    DIRECTION OUTPUT ;
    USE SIGNAL ;
    PORT
      LAYER M4 ;
      RECT 43.116000 30.816000 43.200000 30.840000 ;
    END
  END compiled_identity[9]
  PIN compiled_identity[10]
    DIRECTION OUTPUT ;
    USE SIGNAL ;
    PORT
      LAYER M4 ;
      RECT 43.116000 31.008000 43.200000 31.032000 ;
    END
  END compiled_identity[10]
  PIN compiled_identity[11]
    DIRECTION OUTPUT ;
    USE SIGNAL ;
    PORT
      LAYER M4 ;
      RECT 43.116000 31.200000 43.200000 31.224000 ;
    END
  END compiled_identity[11]
  PIN compiled_identity[12]
    DIRECTION OUTPUT ;
    USE SIGNAL ;
    PORT
      LAYER M4 ;
      RECT 43.116000 31.392000 43.200000 31.416000 ;
    END
  END compiled_identity[12]
  PIN compiled_identity[13]
    DIRECTION OUTPUT ;
    USE SIGNAL ;
    PORT
      LAYER M4 ;
      RECT 43.116000 31.584000 43.200000 31.608000 ;
    END
  END compiled_identity[13]
  PIN compiled_identity[14]
    DIRECTION OUTPUT ;
    USE SIGNAL ;
    PORT
      LAYER M4 ;
      RECT 43.116000 31.776000 43.200000 31.800000 ;
    END
  END compiled_identity[14]
  PIN compiled_identity[15]
    DIRECTION OUTPUT ;
    USE SIGNAL ;
    PORT
      LAYER M4 ;
      RECT 43.116000 31.968000 43.200000 31.992000 ;
    END
  END compiled_identity[15]
  PIN compiled_identity[16]
    DIRECTION OUTPUT ;
    USE SIGNAL ;
    PORT
      LAYER M4 ;
      RECT 43.116000 32.160000 43.200000 32.184000 ;
    END
  END compiled_identity[16]
  PIN compiled_identity[17]
    DIRECTION OUTPUT ;
    USE SIGNAL ;
    PORT
      LAYER M4 ;
      RECT 43.116000 32.352000 43.200000 32.376000 ;
    END
  END compiled_identity[17]
  PIN compiled_identity[18]
    DIRECTION OUTPUT ;
    USE SIGNAL ;
    PORT
      LAYER M4 ;
      RECT 43.116000 32.544000 43.200000 32.568000 ;
    END
  END compiled_identity[18]
  PIN compiled_identity[19]
    DIRECTION OUTPUT ;
    USE SIGNAL ;
    PORT
      LAYER M4 ;
      RECT 43.116000 32.736000 43.200000 32.760000 ;
    END
  END compiled_identity[19]
  PIN compiled_identity[20]
    DIRECTION OUTPUT ;
    USE SIGNAL ;
    PORT
      LAYER M4 ;
      RECT 43.116000 32.928000 43.200000 32.952000 ;
    END
  END compiled_identity[20]
  PIN compiled_identity[21]
    DIRECTION OUTPUT ;
    USE SIGNAL ;
    PORT
      LAYER M4 ;
      RECT 43.116000 33.120000 43.200000 33.144000 ;
    END
  END compiled_identity[21]
  PIN compiled_identity[22]
    DIRECTION OUTPUT ;
    USE SIGNAL ;
    PORT
      LAYER M4 ;
      RECT 43.116000 33.312000 43.200000 33.336000 ;
    END
  END compiled_identity[22]
  PIN compiled_identity[23]
    DIRECTION OUTPUT ;
    USE SIGNAL ;
    PORT
      LAYER M4 ;
      RECT 43.116000 33.504000 43.200000 33.528000 ;
    END
  END compiled_identity[23]
  PIN compiled_identity[24]
    DIRECTION OUTPUT ;
    USE SIGNAL ;
    PORT
      LAYER M4 ;
      RECT 43.116000 33.696000 43.200000 33.720000 ;
    END
  END compiled_identity[24]
  PIN compiled_identity[25]
    DIRECTION OUTPUT ;
    USE SIGNAL ;
    PORT
      LAYER M4 ;
      RECT 43.116000 33.888000 43.200000 33.912000 ;
    END
  END compiled_identity[25]
  PIN compiled_identity[26]
    DIRECTION OUTPUT ;
    USE SIGNAL ;
    PORT
      LAYER M4 ;
      RECT 43.116000 34.080000 43.200000 34.104000 ;
    END
  END compiled_identity[26]
  PIN compiled_identity[27]
    DIRECTION OUTPUT ;
    USE SIGNAL ;
    PORT
      LAYER M4 ;
      RECT 43.116000 34.272000 43.200000 34.296000 ;
    END
  END compiled_identity[27]
  PIN compiled_identity[28]
    DIRECTION OUTPUT ;
    USE SIGNAL ;
    PORT
      LAYER M4 ;
      RECT 43.116000 34.464000 43.200000 34.488000 ;
    END
  END compiled_identity[28]
  PIN compiled_identity[29]
    DIRECTION OUTPUT ;
    USE SIGNAL ;
    PORT
      LAYER M4 ;
      RECT 43.116000 34.656000 43.200000 34.680000 ;
    END
  END compiled_identity[29]
  PIN compiled_identity[30]
    DIRECTION OUTPUT ;
    USE SIGNAL ;
    PORT
      LAYER M4 ;
      RECT 43.116000 34.848000 43.200000 34.872000 ;
    END
  END compiled_identity[30]
  PIN compiled_identity[31]
    DIRECTION OUTPUT ;
    USE SIGNAL ;
    PORT
      LAYER M4 ;
      RECT 43.116000 35.088000 43.200000 35.112000 ;
    END
  END compiled_identity[31]
  PIN compiled_identity[32]
    DIRECTION OUTPUT ;
    USE SIGNAL ;
    PORT
      LAYER M4 ;
      RECT 43.116000 35.280000 43.200000 35.304000 ;
    END
  END compiled_identity[32]
  PIN compiled_identity[33]
    DIRECTION OUTPUT ;
    USE SIGNAL ;
    PORT
      LAYER M4 ;
      RECT 43.116000 35.472000 43.200000 35.496000 ;
    END
  END compiled_identity[33]
  PIN compiled_identity[34]
    DIRECTION OUTPUT ;
    USE SIGNAL ;
    PORT
      LAYER M4 ;
      RECT 43.116000 35.664000 43.200000 35.688000 ;
    END
  END compiled_identity[34]
  PIN compiled_identity[35]
    DIRECTION OUTPUT ;
    USE SIGNAL ;
    PORT
      LAYER M4 ;
      RECT 43.116000 35.856000 43.200000 35.880000 ;
    END
  END compiled_identity[35]
  PIN compiled_identity[36]
    DIRECTION OUTPUT ;
    USE SIGNAL ;
    PORT
      LAYER M4 ;
      RECT 43.116000 36.048000 43.200000 36.072000 ;
    END
  END compiled_identity[36]
  PIN compiled_identity[37]
    DIRECTION OUTPUT ;
    USE SIGNAL ;
    PORT
      LAYER M4 ;
      RECT 43.116000 36.240000 43.200000 36.264000 ;
    END
  END compiled_identity[37]
  PIN compiled_identity[38]
    DIRECTION OUTPUT ;
    USE SIGNAL ;
    PORT
      LAYER M4 ;
      RECT 43.116000 36.432000 43.200000 36.456000 ;
    END
  END compiled_identity[38]
  PIN compiled_identity[39]
    DIRECTION OUTPUT ;
    USE SIGNAL ;
    PORT
      LAYER M4 ;
      RECT 43.116000 36.624000 43.200000 36.648000 ;
    END
  END compiled_identity[39]
  PIN compiled_identity[40]
    DIRECTION OUTPUT ;
    USE SIGNAL ;
    PORT
      LAYER M4 ;
      RECT 43.116000 36.816000 43.200000 36.840000 ;
    END
  END compiled_identity[40]
  PIN compiled_identity[41]
    DIRECTION OUTPUT ;
    USE SIGNAL ;
    PORT
      LAYER M4 ;
      RECT 43.116000 37.008000 43.200000 37.032000 ;
    END
  END compiled_identity[41]
  PIN compiled_identity[42]
    DIRECTION OUTPUT ;
    USE SIGNAL ;
    PORT
      LAYER M4 ;
      RECT 43.116000 37.200000 43.200000 37.224000 ;
    END
  END compiled_identity[42]
  PIN compiled_identity[43]
    DIRECTION OUTPUT ;
    USE SIGNAL ;
    PORT
      LAYER M4 ;
      RECT 43.116000 37.392000 43.200000 37.416000 ;
    END
  END compiled_identity[43]
  PIN compiled_identity[44]
    DIRECTION OUTPUT ;
    USE SIGNAL ;
    PORT
      LAYER M4 ;
      RECT 43.116000 37.584000 43.200000 37.608000 ;
    END
  END compiled_identity[44]
  PIN compiled_identity[45]
    DIRECTION OUTPUT ;
    USE SIGNAL ;
    PORT
      LAYER M4 ;
      RECT 43.116000 37.776000 43.200000 37.800000 ;
    END
  END compiled_identity[45]
  PIN compiled_identity[46]
    DIRECTION OUTPUT ;
    USE SIGNAL ;
    PORT
      LAYER M4 ;
      RECT 43.116000 37.968000 43.200000 37.992000 ;
    END
  END compiled_identity[46]
  PIN compiled_identity[47]
    DIRECTION OUTPUT ;
    USE SIGNAL ;
    PORT
      LAYER M4 ;
      RECT 43.116000 38.160000 43.200000 38.184000 ;
    END
  END compiled_identity[47]
  PIN compiled_identity[48]
    DIRECTION OUTPUT ;
    USE SIGNAL ;
    PORT
      LAYER M4 ;
      RECT 43.116000 38.352000 43.200000 38.376000 ;
    END
  END compiled_identity[48]
  PIN compiled_identity[49]
    DIRECTION OUTPUT ;
    USE SIGNAL ;
    PORT
      LAYER M4 ;
      RECT 43.116000 38.544000 43.200000 38.568000 ;
    END
  END compiled_identity[49]
  PIN compiled_identity[50]
    DIRECTION OUTPUT ;
    USE SIGNAL ;
    PORT
      LAYER M4 ;
      RECT 43.116000 38.736000 43.200000 38.760000 ;
    END
  END compiled_identity[50]
  PIN compiled_identity[51]
    DIRECTION OUTPUT ;
    USE SIGNAL ;
    PORT
      LAYER M4 ;
      RECT 43.116000 38.928000 43.200000 38.952000 ;
    END
  END compiled_identity[51]
  PIN compiled_identity[52]
    DIRECTION OUTPUT ;
    USE SIGNAL ;
    PORT
      LAYER M4 ;
      RECT 43.116000 39.120000 43.200000 39.144000 ;
    END
  END compiled_identity[52]
  PIN compiled_identity[53]
    DIRECTION OUTPUT ;
    USE SIGNAL ;
    PORT
      LAYER M4 ;
      RECT 43.116000 39.312000 43.200000 39.336000 ;
    END
  END compiled_identity[53]
  PIN compiled_identity[54]
    DIRECTION OUTPUT ;
    USE SIGNAL ;
    PORT
      LAYER M4 ;
      RECT 43.116000 39.504000 43.200000 39.528000 ;
    END
  END compiled_identity[54]
  PIN compiled_identity[55]
    DIRECTION OUTPUT ;
    USE SIGNAL ;
    PORT
      LAYER M4 ;
      RECT 43.116000 39.696000 43.200000 39.720000 ;
    END
  END compiled_identity[55]
  PIN compiled_identity[56]
    DIRECTION OUTPUT ;
    USE SIGNAL ;
    PORT
      LAYER M4 ;
      RECT 43.116000 39.936000 43.200000 39.960000 ;
    END
  END compiled_identity[56]
  PIN compiled_identity[57]
    DIRECTION OUTPUT ;
    USE SIGNAL ;
    PORT
      LAYER M4 ;
      RECT 43.116000 40.128000 43.200000 40.152000 ;
    END
  END compiled_identity[57]
  PIN compiled_identity[58]
    DIRECTION OUTPUT ;
    USE SIGNAL ;
    PORT
      LAYER M4 ;
      RECT 43.116000 40.320000 43.200000 40.344000 ;
    END
  END compiled_identity[58]
  PIN compiled_generation[0]
    DIRECTION OUTPUT ;
    USE SIGNAL ;
    PORT
      LAYER M4 ;
      RECT 43.116000 40.512000 43.200000 40.536000 ;
    END
  END compiled_generation[0]
  PIN compiled_generation[1]
    DIRECTION OUTPUT ;
    USE SIGNAL ;
    PORT
      LAYER M4 ;
      RECT 43.116000 40.704000 43.200000 40.728000 ;
    END
  END compiled_generation[1]
  PIN fault
    DIRECTION OUTPUT ;
    USE SIGNAL ;
    PORT
      LAYER M4 ;
      RECT 43.116000 40.896000 43.200000 40.920000 ;
    END
  END fault
END qkd_kvn_ctx_ovl_rope
END LIBRARY
